VERSION 5.7 ;
BUSBITCHARS "[]" ;
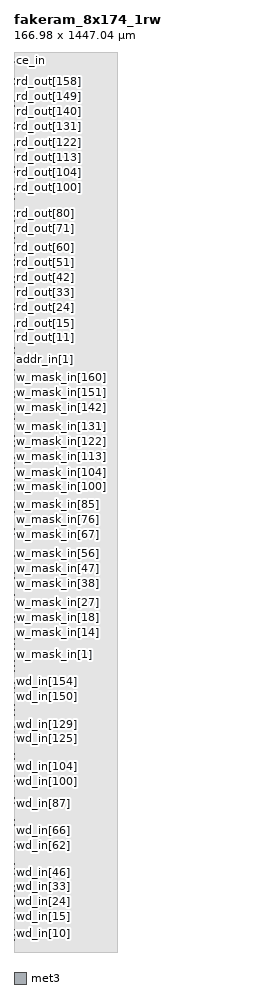
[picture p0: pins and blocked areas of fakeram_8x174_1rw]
MACRO fakeram_8x174_1rw
  FOREIGN fakeram_8x174_1rw 0 0 ;
  SYMMETRY X Y R90 ;
  SIZE 166.980 BY 1447.040 ;
  CLASS BLOCK ;
  PIN wd_in[0]
    DIRECTION INPUT ;
    USE SIGNAL ;
    SHAPE ABUTMENT ;
    PORT
      LAYER met3 ;
      RECT 0.000 2.720 0.300 3.020 ;
    END
  END wd_in[0]
  PIN wd_in[1]
    DIRECTION INPUT ;
    USE SIGNAL ;
    SHAPE ABUTMENT ;
    PORT
      LAYER met3 ;
      RECT 0.000 5.440 0.300 5.740 ;
    END
  END wd_in[1]
  PIN wd_in[2]
    DIRECTION INPUT ;
    USE SIGNAL ;
    SHAPE ABUTMENT ;
    PORT
      LAYER met3 ;
      RECT 0.000 8.160 0.300 8.460 ;
    END
  END wd_in[2]
  PIN wd_in[3]
    DIRECTION INPUT ;
    USE SIGNAL ;
    SHAPE ABUTMENT ;
    PORT
      LAYER met3 ;
      RECT 0.000 10.880 0.300 11.180 ;
    END
  END wd_in[3]
  PIN wd_in[4]
    DIRECTION INPUT ;
    USE SIGNAL ;
    SHAPE ABUTMENT ;
    PORT
      LAYER met3 ;
      RECT 0.000 13.600 0.300 13.900 ;
    END
  END wd_in[4]
  PIN wd_in[5]
    DIRECTION INPUT ;
    USE SIGNAL ;
    SHAPE ABUTMENT ;
    PORT
      LAYER met3 ;
      RECT 0.000 16.320 0.300 16.620 ;
    END
  END wd_in[5]
  PIN wd_in[6]
    DIRECTION INPUT ;
    USE SIGNAL ;
    SHAPE ABUTMENT ;
    PORT
      LAYER met3 ;
      RECT 0.000 19.040 0.300 19.340 ;
    END
  END wd_in[6]
  PIN wd_in[7]
    DIRECTION INPUT ;
    USE SIGNAL ;
    SHAPE ABUTMENT ;
    PORT
      LAYER met3 ;
      RECT 0.000 21.760 0.300 22.060 ;
    END
  END wd_in[7]
  PIN wd_in[8]
    DIRECTION INPUT ;
    USE SIGNAL ;
    SHAPE ABUTMENT ;
    PORT
      LAYER met3 ;
      RECT 0.000 24.480 0.300 24.780 ;
    END
  END wd_in[8]
  PIN wd_in[9]
    DIRECTION INPUT ;
    USE SIGNAL ;
    SHAPE ABUTMENT ;
    PORT
      LAYER met3 ;
      RECT 0.000 27.200 0.300 27.500 ;
    END
  END wd_in[9]
  PIN wd_in[10]
    DIRECTION INPUT ;
    USE SIGNAL ;
    SHAPE ABUTMENT ;
    PORT
      LAYER met3 ;
      RECT 0.000 29.920 0.300 30.220 ;
    END
  END wd_in[10]
  PIN wd_in[11]
    DIRECTION INPUT ;
    USE SIGNAL ;
    SHAPE ABUTMENT ;
    PORT
      LAYER met3 ;
      RECT 0.000 32.640 0.300 32.940 ;
    END
  END wd_in[11]
  PIN wd_in[12]
    DIRECTION INPUT ;
    USE SIGNAL ;
    SHAPE ABUTMENT ;
    PORT
      LAYER met3 ;
      RECT 0.000 35.360 0.300 35.660 ;
    END
  END wd_in[12]
  PIN wd_in[13]
    DIRECTION INPUT ;
    USE SIGNAL ;
    SHAPE ABUTMENT ;
    PORT
      LAYER met3 ;
      RECT 0.000 38.080 0.300 38.380 ;
    END
  END wd_in[13]
  PIN wd_in[14]
    DIRECTION INPUT ;
    USE SIGNAL ;
    SHAPE ABUTMENT ;
    PORT
      LAYER met3 ;
      RECT 0.000 40.800 0.300 41.100 ;
    END
  END wd_in[14]
  PIN wd_in[15]
    DIRECTION INPUT ;
    USE SIGNAL ;
    SHAPE ABUTMENT ;
    PORT
      LAYER met3 ;
      RECT 0.000 43.520 0.300 43.820 ;
    END
  END wd_in[15]
  PIN wd_in[16]
    DIRECTION INPUT ;
    USE SIGNAL ;
    SHAPE ABUTMENT ;
    PORT
      LAYER met3 ;
      RECT 0.000 46.240 0.300 46.540 ;
    END
  END wd_in[16]
  PIN wd_in[17]
    DIRECTION INPUT ;
    USE SIGNAL ;
    SHAPE ABUTMENT ;
    PORT
      LAYER met3 ;
      RECT 0.000 48.960 0.300 49.260 ;
    END
  END wd_in[17]
  PIN wd_in[18]
    DIRECTION INPUT ;
    USE SIGNAL ;
    SHAPE ABUTMENT ;
    PORT
      LAYER met3 ;
      RECT 0.000 51.680 0.300 51.980 ;
    END
  END wd_in[18]
  PIN wd_in[19]
    DIRECTION INPUT ;
    USE SIGNAL ;
    SHAPE ABUTMENT ;
    PORT
      LAYER met3 ;
      RECT 0.000 54.400 0.300 54.700 ;
    END
  END wd_in[19]
  PIN wd_in[20]
    DIRECTION INPUT ;
    USE SIGNAL ;
    SHAPE ABUTMENT ;
    PORT
      LAYER met3 ;
      RECT 0.000 57.120 0.300 57.420 ;
    END
  END wd_in[20]
  PIN wd_in[21]
    DIRECTION INPUT ;
    USE SIGNAL ;
    SHAPE ABUTMENT ;
    PORT
      LAYER met3 ;
      RECT 0.000 59.840 0.300 60.140 ;
    END
  END wd_in[21]
  PIN wd_in[22]
    DIRECTION INPUT ;
    USE SIGNAL ;
    SHAPE ABUTMENT ;
    PORT
      LAYER met3 ;
      RECT 0.000 62.560 0.300 62.860 ;
    END
  END wd_in[22]
  PIN wd_in[23]
    DIRECTION INPUT ;
    USE SIGNAL ;
    SHAPE ABUTMENT ;
    PORT
      LAYER met3 ;
      RECT 0.000 65.280 0.300 65.580 ;
    END
  END wd_in[23]
  PIN wd_in[24]
    DIRECTION INPUT ;
    USE SIGNAL ;
    SHAPE ABUTMENT ;
    PORT
      LAYER met3 ;
      RECT 0.000 68.000 0.300 68.300 ;
    END
  END wd_in[24]
  PIN wd_in[25]
    DIRECTION INPUT ;
    USE SIGNAL ;
    SHAPE ABUTMENT ;
    PORT
      LAYER met3 ;
      RECT 0.000 70.720 0.300 71.020 ;
    END
  END wd_in[25]
  PIN wd_in[26]
    DIRECTION INPUT ;
    USE SIGNAL ;
    SHAPE ABUTMENT ;
    PORT
      LAYER met3 ;
      RECT 0.000 73.440 0.300 73.740 ;
    END
  END wd_in[26]
  PIN wd_in[27]
    DIRECTION INPUT ;
    USE SIGNAL ;
    SHAPE ABUTMENT ;
    PORT
      LAYER met3 ;
      RECT 0.000 76.160 0.300 76.460 ;
    END
  END wd_in[27]
  PIN wd_in[28]
    DIRECTION INPUT ;
    USE SIGNAL ;
    SHAPE ABUTMENT ;
    PORT
      LAYER met3 ;
      RECT 0.000 78.880 0.300 79.180 ;
    END
  END wd_in[28]
  PIN wd_in[29]
    DIRECTION INPUT ;
    USE SIGNAL ;
    SHAPE ABUTMENT ;
    PORT
      LAYER met3 ;
      RECT 0.000 81.600 0.300 81.900 ;
    END
  END wd_in[29]
  PIN wd_in[30]
    DIRECTION INPUT ;
    USE SIGNAL ;
    SHAPE ABUTMENT ;
    PORT
      LAYER met3 ;
      RECT 0.000 84.320 0.300 84.620 ;
    END
  END wd_in[30]
  PIN wd_in[31]
    DIRECTION INPUT ;
    USE SIGNAL ;
    SHAPE ABUTMENT ;
    PORT
      LAYER met3 ;
      RECT 0.000 87.040 0.300 87.340 ;
    END
  END wd_in[31]
  PIN wd_in[32]
    DIRECTION INPUT ;
    USE SIGNAL ;
    SHAPE ABUTMENT ;
    PORT
      LAYER met3 ;
      RECT 0.000 89.760 0.300 90.060 ;
    END
  END wd_in[32]
  PIN wd_in[33]
    DIRECTION INPUT ;
    USE SIGNAL ;
    SHAPE ABUTMENT ;
    PORT
      LAYER met3 ;
      RECT 0.000 92.480 0.300 92.780 ;
    END
  END wd_in[33]
  PIN wd_in[34]
    DIRECTION INPUT ;
    USE SIGNAL ;
    SHAPE ABUTMENT ;
    PORT
      LAYER met3 ;
      RECT 0.000 95.200 0.300 95.500 ;
    END
  END wd_in[34]
  PIN wd_in[35]
    DIRECTION INPUT ;
    USE SIGNAL ;
    SHAPE ABUTMENT ;
    PORT
      LAYER met3 ;
      RECT 0.000 97.920 0.300 98.220 ;
    END
  END wd_in[35]
  PIN wd_in[36]
    DIRECTION INPUT ;
    USE SIGNAL ;
    SHAPE ABUTMENT ;
    PORT
      LAYER met3 ;
      RECT 0.000 100.640 0.300 100.940 ;
    END
  END wd_in[36]
  PIN wd_in[37]
    DIRECTION INPUT ;
    USE SIGNAL ;
    SHAPE ABUTMENT ;
    PORT
      LAYER met3 ;
      RECT 0.000 103.360 0.300 103.660 ;
    END
  END wd_in[37]
  PIN wd_in[38]
    DIRECTION INPUT ;
    USE SIGNAL ;
    SHAPE ABUTMENT ;
    PORT
      LAYER met3 ;
      RECT 0.000 106.080 0.300 106.380 ;
    END
  END wd_in[38]
  PIN wd_in[39]
    DIRECTION INPUT ;
    USE SIGNAL ;
    SHAPE ABUTMENT ;
    PORT
      LAYER met3 ;
      RECT 0.000 108.800 0.300 109.100 ;
    END
  END wd_in[39]
  PIN wd_in[40]
    DIRECTION INPUT ;
    USE SIGNAL ;
    SHAPE ABUTMENT ;
    PORT
      LAYER met3 ;
      RECT 0.000 111.520 0.300 111.820 ;
    END
  END wd_in[40]
  PIN wd_in[41]
    DIRECTION INPUT ;
    USE SIGNAL ;
    SHAPE ABUTMENT ;
    PORT
      LAYER met3 ;
      RECT 0.000 114.240 0.300 114.540 ;
    END
  END wd_in[41]
  PIN wd_in[42]
    DIRECTION INPUT ;
    USE SIGNAL ;
    SHAPE ABUTMENT ;
    PORT
      LAYER met3 ;
      RECT 0.000 116.960 0.300 117.260 ;
    END
  END wd_in[42]
  PIN wd_in[43]
    DIRECTION INPUT ;
    USE SIGNAL ;
    SHAPE ABUTMENT ;
    PORT
      LAYER met3 ;
      RECT 0.000 119.680 0.300 119.980 ;
    END
  END wd_in[43]
  PIN wd_in[44]
    DIRECTION INPUT ;
    USE SIGNAL ;
    SHAPE ABUTMENT ;
    PORT
      LAYER met3 ;
      RECT 0.000 122.400 0.300 122.700 ;
    END
  END wd_in[44]
  PIN wd_in[45]
    DIRECTION INPUT ;
    USE SIGNAL ;
    SHAPE ABUTMENT ;
    PORT
      LAYER met3 ;
      RECT 0.000 125.120 0.300 125.420 ;
    END
  END wd_in[45]
  PIN wd_in[46]
    DIRECTION INPUT ;
    USE SIGNAL ;
    SHAPE ABUTMENT ;
    PORT
      LAYER met3 ;
      RECT 0.000 127.840 0.300 128.140 ;
    END
  END wd_in[46]
  PIN wd_in[47]
    DIRECTION INPUT ;
    USE SIGNAL ;
    SHAPE ABUTMENT ;
    PORT
      LAYER met3 ;
      RECT 0.000 130.560 0.300 130.860 ;
    END
  END wd_in[47]
  PIN wd_in[48]
    DIRECTION INPUT ;
    USE SIGNAL ;
    SHAPE ABUTMENT ;
    PORT
      LAYER met3 ;
      RECT 0.000 133.280 0.300 133.580 ;
    END
  END wd_in[48]
  PIN wd_in[49]
    DIRECTION INPUT ;
    USE SIGNAL ;
    SHAPE ABUTMENT ;
    PORT
      LAYER met3 ;
      RECT 0.000 136.000 0.300 136.300 ;
    END
  END wd_in[49]
  PIN wd_in[50]
    DIRECTION INPUT ;
    USE SIGNAL ;
    SHAPE ABUTMENT ;
    PORT
      LAYER met3 ;
      RECT 0.000 138.720 0.300 139.020 ;
    END
  END wd_in[50]
  PIN wd_in[51]
    DIRECTION INPUT ;
    USE SIGNAL ;
    SHAPE ABUTMENT ;
    PORT
      LAYER met3 ;
      RECT 0.000 141.440 0.300 141.740 ;
    END
  END wd_in[51]
  PIN wd_in[52]
    DIRECTION INPUT ;
    USE SIGNAL ;
    SHAPE ABUTMENT ;
    PORT
      LAYER met3 ;
      RECT 0.000 144.160 0.300 144.460 ;
    END
  END wd_in[52]
  PIN wd_in[53]
    DIRECTION INPUT ;
    USE SIGNAL ;
    SHAPE ABUTMENT ;
    PORT
      LAYER met3 ;
      RECT 0.000 146.880 0.300 147.180 ;
    END
  END wd_in[53]
  PIN wd_in[54]
    DIRECTION INPUT ;
    USE SIGNAL ;
    SHAPE ABUTMENT ;
    PORT
      LAYER met3 ;
      RECT 0.000 149.600 0.300 149.900 ;
    END
  END wd_in[54]
  PIN wd_in[55]
    DIRECTION INPUT ;
    USE SIGNAL ;
    SHAPE ABUTMENT ;
    PORT
      LAYER met3 ;
      RECT 0.000 152.320 0.300 152.620 ;
    END
  END wd_in[55]
  PIN wd_in[56]
    DIRECTION INPUT ;
    USE SIGNAL ;
    SHAPE ABUTMENT ;
    PORT
      LAYER met3 ;
      RECT 0.000 155.040 0.300 155.340 ;
    END
  END wd_in[56]
  PIN wd_in[57]
    DIRECTION INPUT ;
    USE SIGNAL ;
    SHAPE ABUTMENT ;
    PORT
      LAYER met3 ;
      RECT 0.000 157.760 0.300 158.060 ;
    END
  END wd_in[57]
  PIN wd_in[58]
    DIRECTION INPUT ;
    USE SIGNAL ;
    SHAPE ABUTMENT ;
    PORT
      LAYER met3 ;
      RECT 0.000 160.480 0.300 160.780 ;
    END
  END wd_in[58]
  PIN wd_in[59]
    DIRECTION INPUT ;
    USE SIGNAL ;
    SHAPE ABUTMENT ;
    PORT
      LAYER met3 ;
      RECT 0.000 163.200 0.300 163.500 ;
    END
  END wd_in[59]
  PIN wd_in[60]
    DIRECTION INPUT ;
    USE SIGNAL ;
    SHAPE ABUTMENT ;
    PORT
      LAYER met3 ;
      RECT 0.000 165.920 0.300 166.220 ;
    END
  END wd_in[60]
  PIN wd_in[61]
    DIRECTION INPUT ;
    USE SIGNAL ;
    SHAPE ABUTMENT ;
    PORT
      LAYER met3 ;
      RECT 0.000 168.640 0.300 168.940 ;
    END
  END wd_in[61]
  PIN wd_in[62]
    DIRECTION INPUT ;
    USE SIGNAL ;
    SHAPE ABUTMENT ;
    PORT
      LAYER met3 ;
      RECT 0.000 171.360 0.300 171.660 ;
    END
  END wd_in[62]
  PIN wd_in[63]
    DIRECTION INPUT ;
    USE SIGNAL ;
    SHAPE ABUTMENT ;
    PORT
      LAYER met3 ;
      RECT 0.000 174.080 0.300 174.380 ;
    END
  END wd_in[63]
  PIN wd_in[64]
    DIRECTION INPUT ;
    USE SIGNAL ;
    SHAPE ABUTMENT ;
    PORT
      LAYER met3 ;
      RECT 0.000 176.800 0.300 177.100 ;
    END
  END wd_in[64]
  PIN wd_in[65]
    DIRECTION INPUT ;
    USE SIGNAL ;
    SHAPE ABUTMENT ;
    PORT
      LAYER met3 ;
      RECT 0.000 179.520 0.300 179.820 ;
    END
  END wd_in[65]
  PIN wd_in[66]
    DIRECTION INPUT ;
    USE SIGNAL ;
    SHAPE ABUTMENT ;
    PORT
      LAYER met3 ;
      RECT 0.000 182.240 0.300 182.540 ;
    END
  END wd_in[66]
  PIN wd_in[67]
    DIRECTION INPUT ;
    USE SIGNAL ;
    SHAPE ABUTMENT ;
    PORT
      LAYER met3 ;
      RECT 0.000 184.960 0.300 185.260 ;
    END
  END wd_in[67]
  PIN wd_in[68]
    DIRECTION INPUT ;
    USE SIGNAL ;
    SHAPE ABUTMENT ;
    PORT
      LAYER met3 ;
      RECT 0.000 187.680 0.300 187.980 ;
    END
  END wd_in[68]
  PIN wd_in[69]
    DIRECTION INPUT ;
    USE SIGNAL ;
    SHAPE ABUTMENT ;
    PORT
      LAYER met3 ;
      RECT 0.000 190.400 0.300 190.700 ;
    END
  END wd_in[69]
  PIN wd_in[70]
    DIRECTION INPUT ;
    USE SIGNAL ;
    SHAPE ABUTMENT ;
    PORT
      LAYER met3 ;
      RECT 0.000 193.120 0.300 193.420 ;
    END
  END wd_in[70]
  PIN wd_in[71]
    DIRECTION INPUT ;
    USE SIGNAL ;
    SHAPE ABUTMENT ;
    PORT
      LAYER met3 ;
      RECT 0.000 195.840 0.300 196.140 ;
    END
  END wd_in[71]
  PIN wd_in[72]
    DIRECTION INPUT ;
    USE SIGNAL ;
    SHAPE ABUTMENT ;
    PORT
      LAYER met3 ;
      RECT 0.000 198.560 0.300 198.860 ;
    END
  END wd_in[72]
  PIN wd_in[73]
    DIRECTION INPUT ;
    USE SIGNAL ;
    SHAPE ABUTMENT ;
    PORT
      LAYER met3 ;
      RECT 0.000 201.280 0.300 201.580 ;
    END
  END wd_in[73]
  PIN wd_in[74]
    DIRECTION INPUT ;
    USE SIGNAL ;
    SHAPE ABUTMENT ;
    PORT
      LAYER met3 ;
      RECT 0.000 204.000 0.300 204.300 ;
    END
  END wd_in[74]
  PIN wd_in[75]
    DIRECTION INPUT ;
    USE SIGNAL ;
    SHAPE ABUTMENT ;
    PORT
      LAYER met3 ;
      RECT 0.000 206.720 0.300 207.020 ;
    END
  END wd_in[75]
  PIN wd_in[76]
    DIRECTION INPUT ;
    USE SIGNAL ;
    SHAPE ABUTMENT ;
    PORT
      LAYER met3 ;
      RECT 0.000 209.440 0.300 209.740 ;
    END
  END wd_in[76]
  PIN wd_in[77]
    DIRECTION INPUT ;
    USE SIGNAL ;
    SHAPE ABUTMENT ;
    PORT
      LAYER met3 ;
      RECT 0.000 212.160 0.300 212.460 ;
    END
  END wd_in[77]
  PIN wd_in[78]
    DIRECTION INPUT ;
    USE SIGNAL ;
    SHAPE ABUTMENT ;
    PORT
      LAYER met3 ;
      RECT 0.000 214.880 0.300 215.180 ;
    END
  END wd_in[78]
  PIN wd_in[79]
    DIRECTION INPUT ;
    USE SIGNAL ;
    SHAPE ABUTMENT ;
    PORT
      LAYER met3 ;
      RECT 0.000 217.600 0.300 217.900 ;
    END
  END wd_in[79]
  PIN wd_in[80]
    DIRECTION INPUT ;
    USE SIGNAL ;
    SHAPE ABUTMENT ;
    PORT
      LAYER met3 ;
      RECT 0.000 220.320 0.300 220.620 ;
    END
  END wd_in[80]
  PIN wd_in[81]
    DIRECTION INPUT ;
    USE SIGNAL ;
    SHAPE ABUTMENT ;
    PORT
      LAYER met3 ;
      RECT 0.000 223.040 0.300 223.340 ;
    END
  END wd_in[81]
  PIN wd_in[82]
    DIRECTION INPUT ;
    USE SIGNAL ;
    SHAPE ABUTMENT ;
    PORT
      LAYER met3 ;
      RECT 0.000 225.760 0.300 226.060 ;
    END
  END wd_in[82]
  PIN wd_in[83]
    DIRECTION INPUT ;
    USE SIGNAL ;
    SHAPE ABUTMENT ;
    PORT
      LAYER met3 ;
      RECT 0.000 228.480 0.300 228.780 ;
    END
  END wd_in[83]
  PIN wd_in[84]
    DIRECTION INPUT ;
    USE SIGNAL ;
    SHAPE ABUTMENT ;
    PORT
      LAYER met3 ;
      RECT 0.000 231.200 0.300 231.500 ;
    END
  END wd_in[84]
  PIN wd_in[85]
    DIRECTION INPUT ;
    USE SIGNAL ;
    SHAPE ABUTMENT ;
    PORT
      LAYER met3 ;
      RECT 0.000 233.920 0.300 234.220 ;
    END
  END wd_in[85]
  PIN wd_in[86]
    DIRECTION INPUT ;
    USE SIGNAL ;
    SHAPE ABUTMENT ;
    PORT
      LAYER met3 ;
      RECT 0.000 236.640 0.300 236.940 ;
    END
  END wd_in[86]
  PIN wd_in[87]
    DIRECTION INPUT ;
    USE SIGNAL ;
    SHAPE ABUTMENT ;
    PORT
      LAYER met3 ;
      RECT 0.000 239.360 0.300 239.660 ;
    END
  END wd_in[87]
  PIN wd_in[88]
    DIRECTION INPUT ;
    USE SIGNAL ;
    SHAPE ABUTMENT ;
    PORT
      LAYER met3 ;
      RECT 0.000 242.080 0.300 242.380 ;
    END
  END wd_in[88]
  PIN wd_in[89]
    DIRECTION INPUT ;
    USE SIGNAL ;
    SHAPE ABUTMENT ;
    PORT
      LAYER met3 ;
      RECT 0.000 244.800 0.300 245.100 ;
    END
  END wd_in[89]
  PIN wd_in[90]
    DIRECTION INPUT ;
    USE SIGNAL ;
    SHAPE ABUTMENT ;
    PORT
      LAYER met3 ;
      RECT 0.000 247.520 0.300 247.820 ;
    END
  END wd_in[90]
  PIN wd_in[91]
    DIRECTION INPUT ;
    USE SIGNAL ;
    SHAPE ABUTMENT ;
    PORT
      LAYER met3 ;
      RECT 0.000 250.240 0.300 250.540 ;
    END
  END wd_in[91]
  PIN wd_in[92]
    DIRECTION INPUT ;
    USE SIGNAL ;
    SHAPE ABUTMENT ;
    PORT
      LAYER met3 ;
      RECT 0.000 252.960 0.300 253.260 ;
    END
  END wd_in[92]
  PIN wd_in[93]
    DIRECTION INPUT ;
    USE SIGNAL ;
    SHAPE ABUTMENT ;
    PORT
      LAYER met3 ;
      RECT 0.000 255.680 0.300 255.980 ;
    END
  END wd_in[93]
  PIN wd_in[94]
    DIRECTION INPUT ;
    USE SIGNAL ;
    SHAPE ABUTMENT ;
    PORT
      LAYER met3 ;
      RECT 0.000 258.400 0.300 258.700 ;
    END
  END wd_in[94]
  PIN wd_in[95]
    DIRECTION INPUT ;
    USE SIGNAL ;
    SHAPE ABUTMENT ;
    PORT
      LAYER met3 ;
      RECT 0.000 261.120 0.300 261.420 ;
    END
  END wd_in[95]
  PIN wd_in[96]
    DIRECTION INPUT ;
    USE SIGNAL ;
    SHAPE ABUTMENT ;
    PORT
      LAYER met3 ;
      RECT 0.000 263.840 0.300 264.140 ;
    END
  END wd_in[96]
  PIN wd_in[97]
    DIRECTION INPUT ;
    USE SIGNAL ;
    SHAPE ABUTMENT ;
    PORT
      LAYER met3 ;
      RECT 0.000 266.560 0.300 266.860 ;
    END
  END wd_in[97]
  PIN wd_in[98]
    DIRECTION INPUT ;
    USE SIGNAL ;
    SHAPE ABUTMENT ;
    PORT
      LAYER met3 ;
      RECT 0.000 269.280 0.300 269.580 ;
    END
  END wd_in[98]
  PIN wd_in[99]
    DIRECTION INPUT ;
    USE SIGNAL ;
    SHAPE ABUTMENT ;
    PORT
      LAYER met3 ;
      RECT 0.000 272.000 0.300 272.300 ;
    END
  END wd_in[99]
  PIN wd_in[100]
    DIRECTION INPUT ;
    USE SIGNAL ;
    SHAPE ABUTMENT ;
    PORT
      LAYER met3 ;
      RECT 0.000 274.720 0.300 275.020 ;
    END
  END wd_in[100]
  PIN wd_in[101]
    DIRECTION INPUT ;
    USE SIGNAL ;
    SHAPE ABUTMENT ;
    PORT
      LAYER met3 ;
      RECT 0.000 277.440 0.300 277.740 ;
    END
  END wd_in[101]
  PIN wd_in[102]
    DIRECTION INPUT ;
    USE SIGNAL ;
    SHAPE ABUTMENT ;
    PORT
      LAYER met3 ;
      RECT 0.000 280.160 0.300 280.460 ;
    END
  END wd_in[102]
  PIN wd_in[103]
    DIRECTION INPUT ;
    USE SIGNAL ;
    SHAPE ABUTMENT ;
    PORT
      LAYER met3 ;
      RECT 0.000 282.880 0.300 283.180 ;
    END
  END wd_in[103]
  PIN wd_in[104]
    DIRECTION INPUT ;
    USE SIGNAL ;
    SHAPE ABUTMENT ;
    PORT
      LAYER met3 ;
      RECT 0.000 285.600 0.300 285.900 ;
    END
  END wd_in[104]
  PIN wd_in[105]
    DIRECTION INPUT ;
    USE SIGNAL ;
    SHAPE ABUTMENT ;
    PORT
      LAYER met3 ;
      RECT 0.000 288.320 0.300 288.620 ;
    END
  END wd_in[105]
  PIN wd_in[106]
    DIRECTION INPUT ;
    USE SIGNAL ;
    SHAPE ABUTMENT ;
    PORT
      LAYER met3 ;
      RECT 0.000 291.040 0.300 291.340 ;
    END
  END wd_in[106]
  PIN wd_in[107]
    DIRECTION INPUT ;
    USE SIGNAL ;
    SHAPE ABUTMENT ;
    PORT
      LAYER met3 ;
      RECT 0.000 293.760 0.300 294.060 ;
    END
  END wd_in[107]
  PIN wd_in[108]
    DIRECTION INPUT ;
    USE SIGNAL ;
    SHAPE ABUTMENT ;
    PORT
      LAYER met3 ;
      RECT 0.000 296.480 0.300 296.780 ;
    END
  END wd_in[108]
  PIN wd_in[109]
    DIRECTION INPUT ;
    USE SIGNAL ;
    SHAPE ABUTMENT ;
    PORT
      LAYER met3 ;
      RECT 0.000 299.200 0.300 299.500 ;
    END
  END wd_in[109]
  PIN wd_in[110]
    DIRECTION INPUT ;
    USE SIGNAL ;
    SHAPE ABUTMENT ;
    PORT
      LAYER met3 ;
      RECT 0.000 301.920 0.300 302.220 ;
    END
  END wd_in[110]
  PIN wd_in[111]
    DIRECTION INPUT ;
    USE SIGNAL ;
    SHAPE ABUTMENT ;
    PORT
      LAYER met3 ;
      RECT 0.000 304.640 0.300 304.940 ;
    END
  END wd_in[111]
  PIN wd_in[112]
    DIRECTION INPUT ;
    USE SIGNAL ;
    SHAPE ABUTMENT ;
    PORT
      LAYER met3 ;
      RECT 0.000 307.360 0.300 307.660 ;
    END
  END wd_in[112]
  PIN wd_in[113]
    DIRECTION INPUT ;
    USE SIGNAL ;
    SHAPE ABUTMENT ;
    PORT
      LAYER met3 ;
      RECT 0.000 310.080 0.300 310.380 ;
    END
  END wd_in[113]
  PIN wd_in[114]
    DIRECTION INPUT ;
    USE SIGNAL ;
    SHAPE ABUTMENT ;
    PORT
      LAYER met3 ;
      RECT 0.000 312.800 0.300 313.100 ;
    END
  END wd_in[114]
  PIN wd_in[115]
    DIRECTION INPUT ;
    USE SIGNAL ;
    SHAPE ABUTMENT ;
    PORT
      LAYER met3 ;
      RECT 0.000 315.520 0.300 315.820 ;
    END
  END wd_in[115]
  PIN wd_in[116]
    DIRECTION INPUT ;
    USE SIGNAL ;
    SHAPE ABUTMENT ;
    PORT
      LAYER met3 ;
      RECT 0.000 318.240 0.300 318.540 ;
    END
  END wd_in[116]
  PIN wd_in[117]
    DIRECTION INPUT ;
    USE SIGNAL ;
    SHAPE ABUTMENT ;
    PORT
      LAYER met3 ;
      RECT 0.000 320.960 0.300 321.260 ;
    END
  END wd_in[117]
  PIN wd_in[118]
    DIRECTION INPUT ;
    USE SIGNAL ;
    SHAPE ABUTMENT ;
    PORT
      LAYER met3 ;
      RECT 0.000 323.680 0.300 323.980 ;
    END
  END wd_in[118]
  PIN wd_in[119]
    DIRECTION INPUT ;
    USE SIGNAL ;
    SHAPE ABUTMENT ;
    PORT
      LAYER met3 ;
      RECT 0.000 326.400 0.300 326.700 ;
    END
  END wd_in[119]
  PIN wd_in[120]
    DIRECTION INPUT ;
    USE SIGNAL ;
    SHAPE ABUTMENT ;
    PORT
      LAYER met3 ;
      RECT 0.000 329.120 0.300 329.420 ;
    END
  END wd_in[120]
  PIN wd_in[121]
    DIRECTION INPUT ;
    USE SIGNAL ;
    SHAPE ABUTMENT ;
    PORT
      LAYER met3 ;
      RECT 0.000 331.840 0.300 332.140 ;
    END
  END wd_in[121]
  PIN wd_in[122]
    DIRECTION INPUT ;
    USE SIGNAL ;
    SHAPE ABUTMENT ;
    PORT
      LAYER met3 ;
      RECT 0.000 334.560 0.300 334.860 ;
    END
  END wd_in[122]
  PIN wd_in[123]
    DIRECTION INPUT ;
    USE SIGNAL ;
    SHAPE ABUTMENT ;
    PORT
      LAYER met3 ;
      RECT 0.000 337.280 0.300 337.580 ;
    END
  END wd_in[123]
  PIN wd_in[124]
    DIRECTION INPUT ;
    USE SIGNAL ;
    SHAPE ABUTMENT ;
    PORT
      LAYER met3 ;
      RECT 0.000 340.000 0.300 340.300 ;
    END
  END wd_in[124]
  PIN wd_in[125]
    DIRECTION INPUT ;
    USE SIGNAL ;
    SHAPE ABUTMENT ;
    PORT
      LAYER met3 ;
      RECT 0.000 342.720 0.300 343.020 ;
    END
  END wd_in[125]
  PIN wd_in[126]
    DIRECTION INPUT ;
    USE SIGNAL ;
    SHAPE ABUTMENT ;
    PORT
      LAYER met3 ;
      RECT 0.000 345.440 0.300 345.740 ;
    END
  END wd_in[126]
  PIN wd_in[127]
    DIRECTION INPUT ;
    USE SIGNAL ;
    SHAPE ABUTMENT ;
    PORT
      LAYER met3 ;
      RECT 0.000 348.160 0.300 348.460 ;
    END
  END wd_in[127]
  PIN wd_in[128]
    DIRECTION INPUT ;
    USE SIGNAL ;
    SHAPE ABUTMENT ;
    PORT
      LAYER met3 ;
      RECT 0.000 350.880 0.300 351.180 ;
    END
  END wd_in[128]
  PIN wd_in[129]
    DIRECTION INPUT ;
    USE SIGNAL ;
    SHAPE ABUTMENT ;
    PORT
      LAYER met3 ;
      RECT 0.000 353.600 0.300 353.900 ;
    END
  END wd_in[129]
  PIN wd_in[130]
    DIRECTION INPUT ;
    USE SIGNAL ;
    SHAPE ABUTMENT ;
    PORT
      LAYER met3 ;
      RECT 0.000 356.320 0.300 356.620 ;
    END
  END wd_in[130]
  PIN wd_in[131]
    DIRECTION INPUT ;
    USE SIGNAL ;
    SHAPE ABUTMENT ;
    PORT
      LAYER met3 ;
      RECT 0.000 359.040 0.300 359.340 ;
    END
  END wd_in[131]
  PIN wd_in[132]
    DIRECTION INPUT ;
    USE SIGNAL ;
    SHAPE ABUTMENT ;
    PORT
      LAYER met3 ;
      RECT 0.000 361.760 0.300 362.060 ;
    END
  END wd_in[132]
  PIN wd_in[133]
    DIRECTION INPUT ;
    USE SIGNAL ;
    SHAPE ABUTMENT ;
    PORT
      LAYER met3 ;
      RECT 0.000 364.480 0.300 364.780 ;
    END
  END wd_in[133]
  PIN wd_in[134]
    DIRECTION INPUT ;
    USE SIGNAL ;
    SHAPE ABUTMENT ;
    PORT
      LAYER met3 ;
      RECT 0.000 367.200 0.300 367.500 ;
    END
  END wd_in[134]
  PIN wd_in[135]
    DIRECTION INPUT ;
    USE SIGNAL ;
    SHAPE ABUTMENT ;
    PORT
      LAYER met3 ;
      RECT 0.000 369.920 0.300 370.220 ;
    END
  END wd_in[135]
  PIN wd_in[136]
    DIRECTION INPUT ;
    USE SIGNAL ;
    SHAPE ABUTMENT ;
    PORT
      LAYER met3 ;
      RECT 0.000 372.640 0.300 372.940 ;
    END
  END wd_in[136]
  PIN wd_in[137]
    DIRECTION INPUT ;
    USE SIGNAL ;
    SHAPE ABUTMENT ;
    PORT
      LAYER met3 ;
      RECT 0.000 375.360 0.300 375.660 ;
    END
  END wd_in[137]
  PIN wd_in[138]
    DIRECTION INPUT ;
    USE SIGNAL ;
    SHAPE ABUTMENT ;
    PORT
      LAYER met3 ;
      RECT 0.000 378.080 0.300 378.380 ;
    END
  END wd_in[138]
  PIN wd_in[139]
    DIRECTION INPUT ;
    USE SIGNAL ;
    SHAPE ABUTMENT ;
    PORT
      LAYER met3 ;
      RECT 0.000 380.800 0.300 381.100 ;
    END
  END wd_in[139]
  PIN wd_in[140]
    DIRECTION INPUT ;
    USE SIGNAL ;
    SHAPE ABUTMENT ;
    PORT
      LAYER met3 ;
      RECT 0.000 383.520 0.300 383.820 ;
    END
  END wd_in[140]
  PIN wd_in[141]
    DIRECTION INPUT ;
    USE SIGNAL ;
    SHAPE ABUTMENT ;
    PORT
      LAYER met3 ;
      RECT 0.000 386.240 0.300 386.540 ;
    END
  END wd_in[141]
  PIN wd_in[142]
    DIRECTION INPUT ;
    USE SIGNAL ;
    SHAPE ABUTMENT ;
    PORT
      LAYER met3 ;
      RECT 0.000 388.960 0.300 389.260 ;
    END
  END wd_in[142]
  PIN wd_in[143]
    DIRECTION INPUT ;
    USE SIGNAL ;
    SHAPE ABUTMENT ;
    PORT
      LAYER met3 ;
      RECT 0.000 391.680 0.300 391.980 ;
    END
  END wd_in[143]
  PIN wd_in[144]
    DIRECTION INPUT ;
    USE SIGNAL ;
    SHAPE ABUTMENT ;
    PORT
      LAYER met3 ;
      RECT 0.000 394.400 0.300 394.700 ;
    END
  END wd_in[144]
  PIN wd_in[145]
    DIRECTION INPUT ;
    USE SIGNAL ;
    SHAPE ABUTMENT ;
    PORT
      LAYER met3 ;
      RECT 0.000 397.120 0.300 397.420 ;
    END
  END wd_in[145]
  PIN wd_in[146]
    DIRECTION INPUT ;
    USE SIGNAL ;
    SHAPE ABUTMENT ;
    PORT
      LAYER met3 ;
      RECT 0.000 399.840 0.300 400.140 ;
    END
  END wd_in[146]
  PIN wd_in[147]
    DIRECTION INPUT ;
    USE SIGNAL ;
    SHAPE ABUTMENT ;
    PORT
      LAYER met3 ;
      RECT 0.000 402.560 0.300 402.860 ;
    END
  END wd_in[147]
  PIN wd_in[148]
    DIRECTION INPUT ;
    USE SIGNAL ;
    SHAPE ABUTMENT ;
    PORT
      LAYER met3 ;
      RECT 0.000 405.280 0.300 405.580 ;
    END
  END wd_in[148]
  PIN wd_in[149]
    DIRECTION INPUT ;
    USE SIGNAL ;
    SHAPE ABUTMENT ;
    PORT
      LAYER met3 ;
      RECT 0.000 408.000 0.300 408.300 ;
    END
  END wd_in[149]
  PIN wd_in[150]
    DIRECTION INPUT ;
    USE SIGNAL ;
    SHAPE ABUTMENT ;
    PORT
      LAYER met3 ;
      RECT 0.000 410.720 0.300 411.020 ;
    END
  END wd_in[150]
  PIN wd_in[151]
    DIRECTION INPUT ;
    USE SIGNAL ;
    SHAPE ABUTMENT ;
    PORT
      LAYER met3 ;
      RECT 0.000 413.440 0.300 413.740 ;
    END
  END wd_in[151]
  PIN wd_in[152]
    DIRECTION INPUT ;
    USE SIGNAL ;
    SHAPE ABUTMENT ;
    PORT
      LAYER met3 ;
      RECT 0.000 416.160 0.300 416.460 ;
    END
  END wd_in[152]
  PIN wd_in[153]
    DIRECTION INPUT ;
    USE SIGNAL ;
    SHAPE ABUTMENT ;
    PORT
      LAYER met3 ;
      RECT 0.000 418.880 0.300 419.180 ;
    END
  END wd_in[153]
  PIN wd_in[154]
    DIRECTION INPUT ;
    USE SIGNAL ;
    SHAPE ABUTMENT ;
    PORT
      LAYER met3 ;
      RECT 0.000 421.600 0.300 421.900 ;
    END
  END wd_in[154]
  PIN wd_in[155]
    DIRECTION INPUT ;
    USE SIGNAL ;
    SHAPE ABUTMENT ;
    PORT
      LAYER met3 ;
      RECT 0.000 424.320 0.300 424.620 ;
    END
  END wd_in[155]
  PIN wd_in[156]
    DIRECTION INPUT ;
    USE SIGNAL ;
    SHAPE ABUTMENT ;
    PORT
      LAYER met3 ;
      RECT 0.000 427.040 0.300 427.340 ;
    END
  END wd_in[156]
  PIN wd_in[157]
    DIRECTION INPUT ;
    USE SIGNAL ;
    SHAPE ABUTMENT ;
    PORT
      LAYER met3 ;
      RECT 0.000 429.760 0.300 430.060 ;
    END
  END wd_in[157]
  PIN wd_in[158]
    DIRECTION INPUT ;
    USE SIGNAL ;
    SHAPE ABUTMENT ;
    PORT
      LAYER met3 ;
      RECT 0.000 432.480 0.300 432.780 ;
    END
  END wd_in[158]
  PIN wd_in[159]
    DIRECTION INPUT ;
    USE SIGNAL ;
    SHAPE ABUTMENT ;
    PORT
      LAYER met3 ;
      RECT 0.000 435.200 0.300 435.500 ;
    END
  END wd_in[159]
  PIN wd_in[160]
    DIRECTION INPUT ;
    USE SIGNAL ;
    SHAPE ABUTMENT ;
    PORT
      LAYER met3 ;
      RECT 0.000 437.920 0.300 438.220 ;
    END
  END wd_in[160]
  PIN wd_in[161]
    DIRECTION INPUT ;
    USE SIGNAL ;
    SHAPE ABUTMENT ;
    PORT
      LAYER met3 ;
      RECT 0.000 440.640 0.300 440.940 ;
    END
  END wd_in[161]
  PIN wd_in[162]
    DIRECTION INPUT ;
    USE SIGNAL ;
    SHAPE ABUTMENT ;
    PORT
      LAYER met3 ;
      RECT 0.000 443.360 0.300 443.660 ;
    END
  END wd_in[162]
  PIN wd_in[163]
    DIRECTION INPUT ;
    USE SIGNAL ;
    SHAPE ABUTMENT ;
    PORT
      LAYER met3 ;
      RECT 0.000 446.080 0.300 446.380 ;
    END
  END wd_in[163]
  PIN wd_in[164]
    DIRECTION INPUT ;
    USE SIGNAL ;
    SHAPE ABUTMENT ;
    PORT
      LAYER met3 ;
      RECT 0.000 448.800 0.300 449.100 ;
    END
  END wd_in[164]
  PIN wd_in[165]
    DIRECTION INPUT ;
    USE SIGNAL ;
    SHAPE ABUTMENT ;
    PORT
      LAYER met3 ;
      RECT 0.000 451.520 0.300 451.820 ;
    END
  END wd_in[165]
  PIN wd_in[166]
    DIRECTION INPUT ;
    USE SIGNAL ;
    SHAPE ABUTMENT ;
    PORT
      LAYER met3 ;
      RECT 0.000 454.240 0.300 454.540 ;
    END
  END wd_in[166]
  PIN wd_in[167]
    DIRECTION INPUT ;
    USE SIGNAL ;
    SHAPE ABUTMENT ;
    PORT
      LAYER met3 ;
      RECT 0.000 456.960 0.300 457.260 ;
    END
  END wd_in[167]
  PIN wd_in[168]
    DIRECTION INPUT ;
    USE SIGNAL ;
    SHAPE ABUTMENT ;
    PORT
      LAYER met3 ;
      RECT 0.000 459.680 0.300 459.980 ;
    END
  END wd_in[168]
  PIN wd_in[169]
    DIRECTION INPUT ;
    USE SIGNAL ;
    SHAPE ABUTMENT ;
    PORT
      LAYER met3 ;
      RECT 0.000 462.400 0.300 462.700 ;
    END
  END wd_in[169]
  PIN wd_in[170]
    DIRECTION INPUT ;
    USE SIGNAL ;
    SHAPE ABUTMENT ;
    PORT
      LAYER met3 ;
      RECT 0.000 465.120 0.300 465.420 ;
    END
  END wd_in[170]
  PIN wd_in[171]
    DIRECTION INPUT ;
    USE SIGNAL ;
    SHAPE ABUTMENT ;
    PORT
      LAYER met3 ;
      RECT 0.000 467.840 0.300 468.140 ;
    END
  END wd_in[171]
  PIN wd_in[172]
    DIRECTION INPUT ;
    USE SIGNAL ;
    SHAPE ABUTMENT ;
    PORT
      LAYER met3 ;
      RECT 0.000 470.560 0.300 470.860 ;
    END
  END wd_in[172]
  PIN wd_in[173]
    DIRECTION INPUT ;
    USE SIGNAL ;
    SHAPE ABUTMENT ;
    PORT
      LAYER met3 ;
      RECT 0.000 473.280 0.300 473.580 ;
    END
  END wd_in[173]
  PIN w_mask_in[0]
    DIRECTION INPUT ;
    USE SIGNAL ;
    SHAPE ABUTMENT ;
    PORT
      LAYER met3 ;
      RECT 0.000 476.000 0.300 476.300 ;
    END
  END w_mask_in[0]
  PIN w_mask_in[1]
    DIRECTION INPUT ;
    USE SIGNAL ;
    SHAPE ABUTMENT ;
    PORT
      LAYER met3 ;
      RECT 0.000 478.720 0.300 479.020 ;
    END
  END w_mask_in[1]
  PIN w_mask_in[2]
    DIRECTION INPUT ;
    USE SIGNAL ;
    SHAPE ABUTMENT ;
    PORT
      LAYER met3 ;
      RECT 0.000 481.440 0.300 481.740 ;
    END
  END w_mask_in[2]
  PIN w_mask_in[3]
    DIRECTION INPUT ;
    USE SIGNAL ;
    SHAPE ABUTMENT ;
    PORT
      LAYER met3 ;
      RECT 0.000 484.160 0.300 484.460 ;
    END
  END w_mask_in[3]
  PIN w_mask_in[4]
    DIRECTION INPUT ;
    USE SIGNAL ;
    SHAPE ABUTMENT ;
    PORT
      LAYER met3 ;
      RECT 0.000 486.880 0.300 487.180 ;
    END
  END w_mask_in[4]
  PIN w_mask_in[5]
    DIRECTION INPUT ;
    USE SIGNAL ;
    SHAPE ABUTMENT ;
    PORT
      LAYER met3 ;
      RECT 0.000 489.600 0.300 489.900 ;
    END
  END w_mask_in[5]
  PIN w_mask_in[6]
    DIRECTION INPUT ;
    USE SIGNAL ;
    SHAPE ABUTMENT ;
    PORT
      LAYER met3 ;
      RECT 0.000 492.320 0.300 492.620 ;
    END
  END w_mask_in[6]
  PIN w_mask_in[7]
    DIRECTION INPUT ;
    USE SIGNAL ;
    SHAPE ABUTMENT ;
    PORT
      LAYER met3 ;
      RECT 0.000 495.040 0.300 495.340 ;
    END
  END w_mask_in[7]
  PIN w_mask_in[8]
    DIRECTION INPUT ;
    USE SIGNAL ;
    SHAPE ABUTMENT ;
    PORT
      LAYER met3 ;
      RECT 0.000 497.760 0.300 498.060 ;
    END
  END w_mask_in[8]
  PIN w_mask_in[9]
    DIRECTION INPUT ;
    USE SIGNAL ;
    SHAPE ABUTMENT ;
    PORT
      LAYER met3 ;
      RECT 0.000 500.480 0.300 500.780 ;
    END
  END w_mask_in[9]
  PIN w_mask_in[10]
    DIRECTION INPUT ;
    USE SIGNAL ;
    SHAPE ABUTMENT ;
    PORT
      LAYER met3 ;
      RECT 0.000 503.200 0.300 503.500 ;
    END
  END w_mask_in[10]
  PIN w_mask_in[11]
    DIRECTION INPUT ;
    USE SIGNAL ;
    SHAPE ABUTMENT ;
    PORT
      LAYER met3 ;
      RECT 0.000 505.920 0.300 506.220 ;
    END
  END w_mask_in[11]
  PIN w_mask_in[12]
    DIRECTION INPUT ;
    USE SIGNAL ;
    SHAPE ABUTMENT ;
    PORT
      LAYER met3 ;
      RECT 0.000 508.640 0.300 508.940 ;
    END
  END w_mask_in[12]
  PIN w_mask_in[13]
    DIRECTION INPUT ;
    USE SIGNAL ;
    SHAPE ABUTMENT ;
    PORT
      LAYER met3 ;
      RECT 0.000 511.360 0.300 511.660 ;
    END
  END w_mask_in[13]
  PIN w_mask_in[14]
    DIRECTION INPUT ;
    USE SIGNAL ;
    SHAPE ABUTMENT ;
    PORT
      LAYER met3 ;
      RECT 0.000 514.080 0.300 514.380 ;
    END
  END w_mask_in[14]
  PIN w_mask_in[15]
    DIRECTION INPUT ;
    USE SIGNAL ;
    SHAPE ABUTMENT ;
    PORT
      LAYER met3 ;
      RECT 0.000 516.800 0.300 517.100 ;
    END
  END w_mask_in[15]
  PIN w_mask_in[16]
    DIRECTION INPUT ;
    USE SIGNAL ;
    SHAPE ABUTMENT ;
    PORT
      LAYER met3 ;
      RECT 0.000 519.520 0.300 519.820 ;
    END
  END w_mask_in[16]
  PIN w_mask_in[17]
    DIRECTION INPUT ;
    USE SIGNAL ;
    SHAPE ABUTMENT ;
    PORT
      LAYER met3 ;
      RECT 0.000 522.240 0.300 522.540 ;
    END
  END w_mask_in[17]
  PIN w_mask_in[18]
    DIRECTION INPUT ;
    USE SIGNAL ;
    SHAPE ABUTMENT ;
    PORT
      LAYER met3 ;
      RECT 0.000 524.960 0.300 525.260 ;
    END
  END w_mask_in[18]
  PIN w_mask_in[19]
    DIRECTION INPUT ;
    USE SIGNAL ;
    SHAPE ABUTMENT ;
    PORT
      LAYER met3 ;
      RECT 0.000 527.680 0.300 527.980 ;
    END
  END w_mask_in[19]
  PIN w_mask_in[20]
    DIRECTION INPUT ;
    USE SIGNAL ;
    SHAPE ABUTMENT ;
    PORT
      LAYER met3 ;
      RECT 0.000 530.400 0.300 530.700 ;
    END
  END w_mask_in[20]
  PIN w_mask_in[21]
    DIRECTION INPUT ;
    USE SIGNAL ;
    SHAPE ABUTMENT ;
    PORT
      LAYER met3 ;
      RECT 0.000 533.120 0.300 533.420 ;
    END
  END w_mask_in[21]
  PIN w_mask_in[22]
    DIRECTION INPUT ;
    USE SIGNAL ;
    SHAPE ABUTMENT ;
    PORT
      LAYER met3 ;
      RECT 0.000 535.840 0.300 536.140 ;
    END
  END w_mask_in[22]
  PIN w_mask_in[23]
    DIRECTION INPUT ;
    USE SIGNAL ;
    SHAPE ABUTMENT ;
    PORT
      LAYER met3 ;
      RECT 0.000 538.560 0.300 538.860 ;
    END
  END w_mask_in[23]
  PIN w_mask_in[24]
    DIRECTION INPUT ;
    USE SIGNAL ;
    SHAPE ABUTMENT ;
    PORT
      LAYER met3 ;
      RECT 0.000 541.280 0.300 541.580 ;
    END
  END w_mask_in[24]
  PIN w_mask_in[25]
    DIRECTION INPUT ;
    USE SIGNAL ;
    SHAPE ABUTMENT ;
    PORT
      LAYER met3 ;
      RECT 0.000 544.000 0.300 544.300 ;
    END
  END w_mask_in[25]
  PIN w_mask_in[26]
    DIRECTION INPUT ;
    USE SIGNAL ;
    SHAPE ABUTMENT ;
    PORT
      LAYER met3 ;
      RECT 0.000 546.720 0.300 547.020 ;
    END
  END w_mask_in[26]
  PIN w_mask_in[27]
    DIRECTION INPUT ;
    USE SIGNAL ;
    SHAPE ABUTMENT ;
    PORT
      LAYER met3 ;
      RECT 0.000 549.440 0.300 549.740 ;
    END
  END w_mask_in[27]
  PIN w_mask_in[28]
    DIRECTION INPUT ;
    USE SIGNAL ;
    SHAPE ABUTMENT ;
    PORT
      LAYER met3 ;
      RECT 0.000 552.160 0.300 552.460 ;
    END
  END w_mask_in[28]
  PIN w_mask_in[29]
    DIRECTION INPUT ;
    USE SIGNAL ;
    SHAPE ABUTMENT ;
    PORT
      LAYER met3 ;
      RECT 0.000 554.880 0.300 555.180 ;
    END
  END w_mask_in[29]
  PIN w_mask_in[30]
    DIRECTION INPUT ;
    USE SIGNAL ;
    SHAPE ABUTMENT ;
    PORT
      LAYER met3 ;
      RECT 0.000 557.600 0.300 557.900 ;
    END
  END w_mask_in[30]
  PIN w_mask_in[31]
    DIRECTION INPUT ;
    USE SIGNAL ;
    SHAPE ABUTMENT ;
    PORT
      LAYER met3 ;
      RECT 0.000 560.320 0.300 560.620 ;
    END
  END w_mask_in[31]
  PIN w_mask_in[32]
    DIRECTION INPUT ;
    USE SIGNAL ;
    SHAPE ABUTMENT ;
    PORT
      LAYER met3 ;
      RECT 0.000 563.040 0.300 563.340 ;
    END
  END w_mask_in[32]
  PIN w_mask_in[33]
    DIRECTION INPUT ;
    USE SIGNAL ;
    SHAPE ABUTMENT ;
    PORT
      LAYER met3 ;
      RECT 0.000 565.760 0.300 566.060 ;
    END
  END w_mask_in[33]
  PIN w_mask_in[34]
    DIRECTION INPUT ;
    USE SIGNAL ;
    SHAPE ABUTMENT ;
    PORT
      LAYER met3 ;
      RECT 0.000 568.480 0.300 568.780 ;
    END
  END w_mask_in[34]
  PIN w_mask_in[35]
    DIRECTION INPUT ;
    USE SIGNAL ;
    SHAPE ABUTMENT ;
    PORT
      LAYER met3 ;
      RECT 0.000 571.200 0.300 571.500 ;
    END
  END w_mask_in[35]
  PIN w_mask_in[36]
    DIRECTION INPUT ;
    USE SIGNAL ;
    SHAPE ABUTMENT ;
    PORT
      LAYER met3 ;
      RECT 0.000 573.920 0.300 574.220 ;
    END
  END w_mask_in[36]
  PIN w_mask_in[37]
    DIRECTION INPUT ;
    USE SIGNAL ;
    SHAPE ABUTMENT ;
    PORT
      LAYER met3 ;
      RECT 0.000 576.640 0.300 576.940 ;
    END
  END w_mask_in[37]
  PIN w_mask_in[38]
    DIRECTION INPUT ;
    USE SIGNAL ;
    SHAPE ABUTMENT ;
    PORT
      LAYER met3 ;
      RECT 0.000 579.360 0.300 579.660 ;
    END
  END w_mask_in[38]
  PIN w_mask_in[39]
    DIRECTION INPUT ;
    USE SIGNAL ;
    SHAPE ABUTMENT ;
    PORT
      LAYER met3 ;
      RECT 0.000 582.080 0.300 582.380 ;
    END
  END w_mask_in[39]
  PIN w_mask_in[40]
    DIRECTION INPUT ;
    USE SIGNAL ;
    SHAPE ABUTMENT ;
    PORT
      LAYER met3 ;
      RECT 0.000 584.800 0.300 585.100 ;
    END
  END w_mask_in[40]
  PIN w_mask_in[41]
    DIRECTION INPUT ;
    USE SIGNAL ;
    SHAPE ABUTMENT ;
    PORT
      LAYER met3 ;
      RECT 0.000 587.520 0.300 587.820 ;
    END
  END w_mask_in[41]
  PIN w_mask_in[42]
    DIRECTION INPUT ;
    USE SIGNAL ;
    SHAPE ABUTMENT ;
    PORT
      LAYER met3 ;
      RECT 0.000 590.240 0.300 590.540 ;
    END
  END w_mask_in[42]
  PIN w_mask_in[43]
    DIRECTION INPUT ;
    USE SIGNAL ;
    SHAPE ABUTMENT ;
    PORT
      LAYER met3 ;
      RECT 0.000 592.960 0.300 593.260 ;
    END
  END w_mask_in[43]
  PIN w_mask_in[44]
    DIRECTION INPUT ;
    USE SIGNAL ;
    SHAPE ABUTMENT ;
    PORT
      LAYER met3 ;
      RECT 0.000 595.680 0.300 595.980 ;
    END
  END w_mask_in[44]
  PIN w_mask_in[45]
    DIRECTION INPUT ;
    USE SIGNAL ;
    SHAPE ABUTMENT ;
    PORT
      LAYER met3 ;
      RECT 0.000 598.400 0.300 598.700 ;
    END
  END w_mask_in[45]
  PIN w_mask_in[46]
    DIRECTION INPUT ;
    USE SIGNAL ;
    SHAPE ABUTMENT ;
    PORT
      LAYER met3 ;
      RECT 0.000 601.120 0.300 601.420 ;
    END
  END w_mask_in[46]
  PIN w_mask_in[47]
    DIRECTION INPUT ;
    USE SIGNAL ;
    SHAPE ABUTMENT ;
    PORT
      LAYER met3 ;
      RECT 0.000 603.840 0.300 604.140 ;
    END
  END w_mask_in[47]
  PIN w_mask_in[48]
    DIRECTION INPUT ;
    USE SIGNAL ;
    SHAPE ABUTMENT ;
    PORT
      LAYER met3 ;
      RECT 0.000 606.560 0.300 606.860 ;
    END
  END w_mask_in[48]
  PIN w_mask_in[49]
    DIRECTION INPUT ;
    USE SIGNAL ;
    SHAPE ABUTMENT ;
    PORT
      LAYER met3 ;
      RECT 0.000 609.280 0.300 609.580 ;
    END
  END w_mask_in[49]
  PIN w_mask_in[50]
    DIRECTION INPUT ;
    USE SIGNAL ;
    SHAPE ABUTMENT ;
    PORT
      LAYER met3 ;
      RECT 0.000 612.000 0.300 612.300 ;
    END
  END w_mask_in[50]
  PIN w_mask_in[51]
    DIRECTION INPUT ;
    USE SIGNAL ;
    SHAPE ABUTMENT ;
    PORT
      LAYER met3 ;
      RECT 0.000 614.720 0.300 615.020 ;
    END
  END w_mask_in[51]
  PIN w_mask_in[52]
    DIRECTION INPUT ;
    USE SIGNAL ;
    SHAPE ABUTMENT ;
    PORT
      LAYER met3 ;
      RECT 0.000 617.440 0.300 617.740 ;
    END
  END w_mask_in[52]
  PIN w_mask_in[53]
    DIRECTION INPUT ;
    USE SIGNAL ;
    SHAPE ABUTMENT ;
    PORT
      LAYER met3 ;
      RECT 0.000 620.160 0.300 620.460 ;
    END
  END w_mask_in[53]
  PIN w_mask_in[54]
    DIRECTION INPUT ;
    USE SIGNAL ;
    SHAPE ABUTMENT ;
    PORT
      LAYER met3 ;
      RECT 0.000 622.880 0.300 623.180 ;
    END
  END w_mask_in[54]
  PIN w_mask_in[55]
    DIRECTION INPUT ;
    USE SIGNAL ;
    SHAPE ABUTMENT ;
    PORT
      LAYER met3 ;
      RECT 0.000 625.600 0.300 625.900 ;
    END
  END w_mask_in[55]
  PIN w_mask_in[56]
    DIRECTION INPUT ;
    USE SIGNAL ;
    SHAPE ABUTMENT ;
    PORT
      LAYER met3 ;
      RECT 0.000 628.320 0.300 628.620 ;
    END
  END w_mask_in[56]
  PIN w_mask_in[57]
    DIRECTION INPUT ;
    USE SIGNAL ;
    SHAPE ABUTMENT ;
    PORT
      LAYER met3 ;
      RECT 0.000 631.040 0.300 631.340 ;
    END
  END w_mask_in[57]
  PIN w_mask_in[58]
    DIRECTION INPUT ;
    USE SIGNAL ;
    SHAPE ABUTMENT ;
    PORT
      LAYER met3 ;
      RECT 0.000 633.760 0.300 634.060 ;
    END
  END w_mask_in[58]
  PIN w_mask_in[59]
    DIRECTION INPUT ;
    USE SIGNAL ;
    SHAPE ABUTMENT ;
    PORT
      LAYER met3 ;
      RECT 0.000 636.480 0.300 636.780 ;
    END
  END w_mask_in[59]
  PIN w_mask_in[60]
    DIRECTION INPUT ;
    USE SIGNAL ;
    SHAPE ABUTMENT ;
    PORT
      LAYER met3 ;
      RECT 0.000 639.200 0.300 639.500 ;
    END
  END w_mask_in[60]
  PIN w_mask_in[61]
    DIRECTION INPUT ;
    USE SIGNAL ;
    SHAPE ABUTMENT ;
    PORT
      LAYER met3 ;
      RECT 0.000 641.920 0.300 642.220 ;
    END
  END w_mask_in[61]
  PIN w_mask_in[62]
    DIRECTION INPUT ;
    USE SIGNAL ;
    SHAPE ABUTMENT ;
    PORT
      LAYER met3 ;
      RECT 0.000 644.640 0.300 644.940 ;
    END
  END w_mask_in[62]
  PIN w_mask_in[63]
    DIRECTION INPUT ;
    USE SIGNAL ;
    SHAPE ABUTMENT ;
    PORT
      LAYER met3 ;
      RECT 0.000 647.360 0.300 647.660 ;
    END
  END w_mask_in[63]
  PIN w_mask_in[64]
    DIRECTION INPUT ;
    USE SIGNAL ;
    SHAPE ABUTMENT ;
    PORT
      LAYER met3 ;
      RECT 0.000 650.080 0.300 650.380 ;
    END
  END w_mask_in[64]
  PIN w_mask_in[65]
    DIRECTION INPUT ;
    USE SIGNAL ;
    SHAPE ABUTMENT ;
    PORT
      LAYER met3 ;
      RECT 0.000 652.800 0.300 653.100 ;
    END
  END w_mask_in[65]
  PIN w_mask_in[66]
    DIRECTION INPUT ;
    USE SIGNAL ;
    SHAPE ABUTMENT ;
    PORT
      LAYER met3 ;
      RECT 0.000 655.520 0.300 655.820 ;
    END
  END w_mask_in[66]
  PIN w_mask_in[67]
    DIRECTION INPUT ;
    USE SIGNAL ;
    SHAPE ABUTMENT ;
    PORT
      LAYER met3 ;
      RECT 0.000 658.240 0.300 658.540 ;
    END
  END w_mask_in[67]
  PIN w_mask_in[68]
    DIRECTION INPUT ;
    USE SIGNAL ;
    SHAPE ABUTMENT ;
    PORT
      LAYER met3 ;
      RECT 0.000 660.960 0.300 661.260 ;
    END
  END w_mask_in[68]
  PIN w_mask_in[69]
    DIRECTION INPUT ;
    USE SIGNAL ;
    SHAPE ABUTMENT ;
    PORT
      LAYER met3 ;
      RECT 0.000 663.680 0.300 663.980 ;
    END
  END w_mask_in[69]
  PIN w_mask_in[70]
    DIRECTION INPUT ;
    USE SIGNAL ;
    SHAPE ABUTMENT ;
    PORT
      LAYER met3 ;
      RECT 0.000 666.400 0.300 666.700 ;
    END
  END w_mask_in[70]
  PIN w_mask_in[71]
    DIRECTION INPUT ;
    USE SIGNAL ;
    SHAPE ABUTMENT ;
    PORT
      LAYER met3 ;
      RECT 0.000 669.120 0.300 669.420 ;
    END
  END w_mask_in[71]
  PIN w_mask_in[72]
    DIRECTION INPUT ;
    USE SIGNAL ;
    SHAPE ABUTMENT ;
    PORT
      LAYER met3 ;
      RECT 0.000 671.840 0.300 672.140 ;
    END
  END w_mask_in[72]
  PIN w_mask_in[73]
    DIRECTION INPUT ;
    USE SIGNAL ;
    SHAPE ABUTMENT ;
    PORT
      LAYER met3 ;
      RECT 0.000 674.560 0.300 674.860 ;
    END
  END w_mask_in[73]
  PIN w_mask_in[74]
    DIRECTION INPUT ;
    USE SIGNAL ;
    SHAPE ABUTMENT ;
    PORT
      LAYER met3 ;
      RECT 0.000 677.280 0.300 677.580 ;
    END
  END w_mask_in[74]
  PIN w_mask_in[75]
    DIRECTION INPUT ;
    USE SIGNAL ;
    SHAPE ABUTMENT ;
    PORT
      LAYER met3 ;
      RECT 0.000 680.000 0.300 680.300 ;
    END
  END w_mask_in[75]
  PIN w_mask_in[76]
    DIRECTION INPUT ;
    USE SIGNAL ;
    SHAPE ABUTMENT ;
    PORT
      LAYER met3 ;
      RECT 0.000 682.720 0.300 683.020 ;
    END
  END w_mask_in[76]
  PIN w_mask_in[77]
    DIRECTION INPUT ;
    USE SIGNAL ;
    SHAPE ABUTMENT ;
    PORT
      LAYER met3 ;
      RECT 0.000 685.440 0.300 685.740 ;
    END
  END w_mask_in[77]
  PIN w_mask_in[78]
    DIRECTION INPUT ;
    USE SIGNAL ;
    SHAPE ABUTMENT ;
    PORT
      LAYER met3 ;
      RECT 0.000 688.160 0.300 688.460 ;
    END
  END w_mask_in[78]
  PIN w_mask_in[79]
    DIRECTION INPUT ;
    USE SIGNAL ;
    SHAPE ABUTMENT ;
    PORT
      LAYER met3 ;
      RECT 0.000 690.880 0.300 691.180 ;
    END
  END w_mask_in[79]
  PIN w_mask_in[80]
    DIRECTION INPUT ;
    USE SIGNAL ;
    SHAPE ABUTMENT ;
    PORT
      LAYER met3 ;
      RECT 0.000 693.600 0.300 693.900 ;
    END
  END w_mask_in[80]
  PIN w_mask_in[81]
    DIRECTION INPUT ;
    USE SIGNAL ;
    SHAPE ABUTMENT ;
    PORT
      LAYER met3 ;
      RECT 0.000 696.320 0.300 696.620 ;
    END
  END w_mask_in[81]
  PIN w_mask_in[82]
    DIRECTION INPUT ;
    USE SIGNAL ;
    SHAPE ABUTMENT ;
    PORT
      LAYER met3 ;
      RECT 0.000 699.040 0.300 699.340 ;
    END
  END w_mask_in[82]
  PIN w_mask_in[83]
    DIRECTION INPUT ;
    USE SIGNAL ;
    SHAPE ABUTMENT ;
    PORT
      LAYER met3 ;
      RECT 0.000 701.760 0.300 702.060 ;
    END
  END w_mask_in[83]
  PIN w_mask_in[84]
    DIRECTION INPUT ;
    USE SIGNAL ;
    SHAPE ABUTMENT ;
    PORT
      LAYER met3 ;
      RECT 0.000 704.480 0.300 704.780 ;
    END
  END w_mask_in[84]
  PIN w_mask_in[85]
    DIRECTION INPUT ;
    USE SIGNAL ;
    SHAPE ABUTMENT ;
    PORT
      LAYER met3 ;
      RECT 0.000 707.200 0.300 707.500 ;
    END
  END w_mask_in[85]
  PIN w_mask_in[86]
    DIRECTION INPUT ;
    USE SIGNAL ;
    SHAPE ABUTMENT ;
    PORT
      LAYER met3 ;
      RECT 0.000 709.920 0.300 710.220 ;
    END
  END w_mask_in[86]
  PIN w_mask_in[87]
    DIRECTION INPUT ;
    USE SIGNAL ;
    SHAPE ABUTMENT ;
    PORT
      LAYER met3 ;
      RECT 0.000 712.640 0.300 712.940 ;
    END
  END w_mask_in[87]
  PIN w_mask_in[88]
    DIRECTION INPUT ;
    USE SIGNAL ;
    SHAPE ABUTMENT ;
    PORT
      LAYER met3 ;
      RECT 0.000 715.360 0.300 715.660 ;
    END
  END w_mask_in[88]
  PIN w_mask_in[89]
    DIRECTION INPUT ;
    USE SIGNAL ;
    SHAPE ABUTMENT ;
    PORT
      LAYER met3 ;
      RECT 0.000 718.080 0.300 718.380 ;
    END
  END w_mask_in[89]
  PIN w_mask_in[90]
    DIRECTION INPUT ;
    USE SIGNAL ;
    SHAPE ABUTMENT ;
    PORT
      LAYER met3 ;
      RECT 0.000 720.800 0.300 721.100 ;
    END
  END w_mask_in[90]
  PIN w_mask_in[91]
    DIRECTION INPUT ;
    USE SIGNAL ;
    SHAPE ABUTMENT ;
    PORT
      LAYER met3 ;
      RECT 0.000 723.520 0.300 723.820 ;
    END
  END w_mask_in[91]
  PIN w_mask_in[92]
    DIRECTION INPUT ;
    USE SIGNAL ;
    SHAPE ABUTMENT ;
    PORT
      LAYER met3 ;
      RECT 0.000 726.240 0.300 726.540 ;
    END
  END w_mask_in[92]
  PIN w_mask_in[93]
    DIRECTION INPUT ;
    USE SIGNAL ;
    SHAPE ABUTMENT ;
    PORT
      LAYER met3 ;
      RECT 0.000 728.960 0.300 729.260 ;
    END
  END w_mask_in[93]
  PIN w_mask_in[94]
    DIRECTION INPUT ;
    USE SIGNAL ;
    SHAPE ABUTMENT ;
    PORT
      LAYER met3 ;
      RECT 0.000 731.680 0.300 731.980 ;
    END
  END w_mask_in[94]
  PIN w_mask_in[95]
    DIRECTION INPUT ;
    USE SIGNAL ;
    SHAPE ABUTMENT ;
    PORT
      LAYER met3 ;
      RECT 0.000 734.400 0.300 734.700 ;
    END
  END w_mask_in[95]
  PIN w_mask_in[96]
    DIRECTION INPUT ;
    USE SIGNAL ;
    SHAPE ABUTMENT ;
    PORT
      LAYER met3 ;
      RECT 0.000 737.120 0.300 737.420 ;
    END
  END w_mask_in[96]
  PIN w_mask_in[97]
    DIRECTION INPUT ;
    USE SIGNAL ;
    SHAPE ABUTMENT ;
    PORT
      LAYER met3 ;
      RECT 0.000 739.840 0.300 740.140 ;
    END
  END w_mask_in[97]
  PIN w_mask_in[98]
    DIRECTION INPUT ;
    USE SIGNAL ;
    SHAPE ABUTMENT ;
    PORT
      LAYER met3 ;
      RECT 0.000 742.560 0.300 742.860 ;
    END
  END w_mask_in[98]
  PIN w_mask_in[99]
    DIRECTION INPUT ;
    USE SIGNAL ;
    SHAPE ABUTMENT ;
    PORT
      LAYER met3 ;
      RECT 0.000 745.280 0.300 745.580 ;
    END
  END w_mask_in[99]
  PIN w_mask_in[100]
    DIRECTION INPUT ;
    USE SIGNAL ;
    SHAPE ABUTMENT ;
    PORT
      LAYER met3 ;
      RECT 0.000 748.000 0.300 748.300 ;
    END
  END w_mask_in[100]
  PIN w_mask_in[101]
    DIRECTION INPUT ;
    USE SIGNAL ;
    SHAPE ABUTMENT ;
    PORT
      LAYER met3 ;
      RECT 0.000 750.720 0.300 751.020 ;
    END
  END w_mask_in[101]
  PIN w_mask_in[102]
    DIRECTION INPUT ;
    USE SIGNAL ;
    SHAPE ABUTMENT ;
    PORT
      LAYER met3 ;
      RECT 0.000 753.440 0.300 753.740 ;
    END
  END w_mask_in[102]
  PIN w_mask_in[103]
    DIRECTION INPUT ;
    USE SIGNAL ;
    SHAPE ABUTMENT ;
    PORT
      LAYER met3 ;
      RECT 0.000 756.160 0.300 756.460 ;
    END
  END w_mask_in[103]
  PIN w_mask_in[104]
    DIRECTION INPUT ;
    USE SIGNAL ;
    SHAPE ABUTMENT ;
    PORT
      LAYER met3 ;
      RECT 0.000 758.880 0.300 759.180 ;
    END
  END w_mask_in[104]
  PIN w_mask_in[105]
    DIRECTION INPUT ;
    USE SIGNAL ;
    SHAPE ABUTMENT ;
    PORT
      LAYER met3 ;
      RECT 0.000 761.600 0.300 761.900 ;
    END
  END w_mask_in[105]
  PIN w_mask_in[106]
    DIRECTION INPUT ;
    USE SIGNAL ;
    SHAPE ABUTMENT ;
    PORT
      LAYER met3 ;
      RECT 0.000 764.320 0.300 764.620 ;
    END
  END w_mask_in[106]
  PIN w_mask_in[107]
    DIRECTION INPUT ;
    USE SIGNAL ;
    SHAPE ABUTMENT ;
    PORT
      LAYER met3 ;
      RECT 0.000 767.040 0.300 767.340 ;
    END
  END w_mask_in[107]
  PIN w_mask_in[108]
    DIRECTION INPUT ;
    USE SIGNAL ;
    SHAPE ABUTMENT ;
    PORT
      LAYER met3 ;
      RECT 0.000 769.760 0.300 770.060 ;
    END
  END w_mask_in[108]
  PIN w_mask_in[109]
    DIRECTION INPUT ;
    USE SIGNAL ;
    SHAPE ABUTMENT ;
    PORT
      LAYER met3 ;
      RECT 0.000 772.480 0.300 772.780 ;
    END
  END w_mask_in[109]
  PIN w_mask_in[110]
    DIRECTION INPUT ;
    USE SIGNAL ;
    SHAPE ABUTMENT ;
    PORT
      LAYER met3 ;
      RECT 0.000 775.200 0.300 775.500 ;
    END
  END w_mask_in[110]
  PIN w_mask_in[111]
    DIRECTION INPUT ;
    USE SIGNAL ;
    SHAPE ABUTMENT ;
    PORT
      LAYER met3 ;
      RECT 0.000 777.920 0.300 778.220 ;
    END
  END w_mask_in[111]
  PIN w_mask_in[112]
    DIRECTION INPUT ;
    USE SIGNAL ;
    SHAPE ABUTMENT ;
    PORT
      LAYER met3 ;
      RECT 0.000 780.640 0.300 780.940 ;
    END
  END w_mask_in[112]
  PIN w_mask_in[113]
    DIRECTION INPUT ;
    USE SIGNAL ;
    SHAPE ABUTMENT ;
    PORT
      LAYER met3 ;
      RECT 0.000 783.360 0.300 783.660 ;
    END
  END w_mask_in[113]
  PIN w_mask_in[114]
    DIRECTION INPUT ;
    USE SIGNAL ;
    SHAPE ABUTMENT ;
    PORT
      LAYER met3 ;
      RECT 0.000 786.080 0.300 786.380 ;
    END
  END w_mask_in[114]
  PIN w_mask_in[115]
    DIRECTION INPUT ;
    USE SIGNAL ;
    SHAPE ABUTMENT ;
    PORT
      LAYER met3 ;
      RECT 0.000 788.800 0.300 789.100 ;
    END
  END w_mask_in[115]
  PIN w_mask_in[116]
    DIRECTION INPUT ;
    USE SIGNAL ;
    SHAPE ABUTMENT ;
    PORT
      LAYER met3 ;
      RECT 0.000 791.520 0.300 791.820 ;
    END
  END w_mask_in[116]
  PIN w_mask_in[117]
    DIRECTION INPUT ;
    USE SIGNAL ;
    SHAPE ABUTMENT ;
    PORT
      LAYER met3 ;
      RECT 0.000 794.240 0.300 794.540 ;
    END
  END w_mask_in[117]
  PIN w_mask_in[118]
    DIRECTION INPUT ;
    USE SIGNAL ;
    SHAPE ABUTMENT ;
    PORT
      LAYER met3 ;
      RECT 0.000 796.960 0.300 797.260 ;
    END
  END w_mask_in[118]
  PIN w_mask_in[119]
    DIRECTION INPUT ;
    USE SIGNAL ;
    SHAPE ABUTMENT ;
    PORT
      LAYER met3 ;
      RECT 0.000 799.680 0.300 799.980 ;
    END
  END w_mask_in[119]
  PIN w_mask_in[120]
    DIRECTION INPUT ;
    USE SIGNAL ;
    SHAPE ABUTMENT ;
    PORT
      LAYER met3 ;
      RECT 0.000 802.400 0.300 802.700 ;
    END
  END w_mask_in[120]
  PIN w_mask_in[121]
    DIRECTION INPUT ;
    USE SIGNAL ;
    SHAPE ABUTMENT ;
    PORT
      LAYER met3 ;
      RECT 0.000 805.120 0.300 805.420 ;
    END
  END w_mask_in[121]
  PIN w_mask_in[122]
    DIRECTION INPUT ;
    USE SIGNAL ;
    SHAPE ABUTMENT ;
    PORT
      LAYER met3 ;
      RECT 0.000 807.840 0.300 808.140 ;
    END
  END w_mask_in[122]
  PIN w_mask_in[123]
    DIRECTION INPUT ;
    USE SIGNAL ;
    SHAPE ABUTMENT ;
    PORT
      LAYER met3 ;
      RECT 0.000 810.560 0.300 810.860 ;
    END
  END w_mask_in[123]
  PIN w_mask_in[124]
    DIRECTION INPUT ;
    USE SIGNAL ;
    SHAPE ABUTMENT ;
    PORT
      LAYER met3 ;
      RECT 0.000 813.280 0.300 813.580 ;
    END
  END w_mask_in[124]
  PIN w_mask_in[125]
    DIRECTION INPUT ;
    USE SIGNAL ;
    SHAPE ABUTMENT ;
    PORT
      LAYER met3 ;
      RECT 0.000 816.000 0.300 816.300 ;
    END
  END w_mask_in[125]
  PIN w_mask_in[126]
    DIRECTION INPUT ;
    USE SIGNAL ;
    SHAPE ABUTMENT ;
    PORT
      LAYER met3 ;
      RECT 0.000 818.720 0.300 819.020 ;
    END
  END w_mask_in[126]
  PIN w_mask_in[127]
    DIRECTION INPUT ;
    USE SIGNAL ;
    SHAPE ABUTMENT ;
    PORT
      LAYER met3 ;
      RECT 0.000 821.440 0.300 821.740 ;
    END
  END w_mask_in[127]
  PIN w_mask_in[128]
    DIRECTION INPUT ;
    USE SIGNAL ;
    SHAPE ABUTMENT ;
    PORT
      LAYER met3 ;
      RECT 0.000 824.160 0.300 824.460 ;
    END
  END w_mask_in[128]
  PIN w_mask_in[129]
    DIRECTION INPUT ;
    USE SIGNAL ;
    SHAPE ABUTMENT ;
    PORT
      LAYER met3 ;
      RECT 0.000 826.880 0.300 827.180 ;
    END
  END w_mask_in[129]
  PIN w_mask_in[130]
    DIRECTION INPUT ;
    USE SIGNAL ;
    SHAPE ABUTMENT ;
    PORT
      LAYER met3 ;
      RECT 0.000 829.600 0.300 829.900 ;
    END
  END w_mask_in[130]
  PIN w_mask_in[131]
    DIRECTION INPUT ;
    USE SIGNAL ;
    SHAPE ABUTMENT ;
    PORT
      LAYER met3 ;
      RECT 0.000 832.320 0.300 832.620 ;
    END
  END w_mask_in[131]
  PIN w_mask_in[132]
    DIRECTION INPUT ;
    USE SIGNAL ;
    SHAPE ABUTMENT ;
    PORT
      LAYER met3 ;
      RECT 0.000 835.040 0.300 835.340 ;
    END
  END w_mask_in[132]
  PIN w_mask_in[133]
    DIRECTION INPUT ;
    USE SIGNAL ;
    SHAPE ABUTMENT ;
    PORT
      LAYER met3 ;
      RECT 0.000 837.760 0.300 838.060 ;
    END
  END w_mask_in[133]
  PIN w_mask_in[134]
    DIRECTION INPUT ;
    USE SIGNAL ;
    SHAPE ABUTMENT ;
    PORT
      LAYER met3 ;
      RECT 0.000 840.480 0.300 840.780 ;
    END
  END w_mask_in[134]
  PIN w_mask_in[135]
    DIRECTION INPUT ;
    USE SIGNAL ;
    SHAPE ABUTMENT ;
    PORT
      LAYER met3 ;
      RECT 0.000 843.200 0.300 843.500 ;
    END
  END w_mask_in[135]
  PIN w_mask_in[136]
    DIRECTION INPUT ;
    USE SIGNAL ;
    SHAPE ABUTMENT ;
    PORT
      LAYER met3 ;
      RECT 0.000 845.920 0.300 846.220 ;
    END
  END w_mask_in[136]
  PIN w_mask_in[137]
    DIRECTION INPUT ;
    USE SIGNAL ;
    SHAPE ABUTMENT ;
    PORT
      LAYER met3 ;
      RECT 0.000 848.640 0.300 848.940 ;
    END
  END w_mask_in[137]
  PIN w_mask_in[138]
    DIRECTION INPUT ;
    USE SIGNAL ;
    SHAPE ABUTMENT ;
    PORT
      LAYER met3 ;
      RECT 0.000 851.360 0.300 851.660 ;
    END
  END w_mask_in[138]
  PIN w_mask_in[139]
    DIRECTION INPUT ;
    USE SIGNAL ;
    SHAPE ABUTMENT ;
    PORT
      LAYER met3 ;
      RECT 0.000 854.080 0.300 854.380 ;
    END
  END w_mask_in[139]
  PIN w_mask_in[140]
    DIRECTION INPUT ;
    USE SIGNAL ;
    SHAPE ABUTMENT ;
    PORT
      LAYER met3 ;
      RECT 0.000 856.800 0.300 857.100 ;
    END
  END w_mask_in[140]
  PIN w_mask_in[141]
    DIRECTION INPUT ;
    USE SIGNAL ;
    SHAPE ABUTMENT ;
    PORT
      LAYER met3 ;
      RECT 0.000 859.520 0.300 859.820 ;
    END
  END w_mask_in[141]
  PIN w_mask_in[142]
    DIRECTION INPUT ;
    USE SIGNAL ;
    SHAPE ABUTMENT ;
    PORT
      LAYER met3 ;
      RECT 0.000 862.240 0.300 862.540 ;
    END
  END w_mask_in[142]
  PIN w_mask_in[143]
    DIRECTION INPUT ;
    USE SIGNAL ;
    SHAPE ABUTMENT ;
    PORT
      LAYER met3 ;
      RECT 0.000 864.960 0.300 865.260 ;
    END
  END w_mask_in[143]
  PIN w_mask_in[144]
    DIRECTION INPUT ;
    USE SIGNAL ;
    SHAPE ABUTMENT ;
    PORT
      LAYER met3 ;
      RECT 0.000 867.680 0.300 867.980 ;
    END
  END w_mask_in[144]
  PIN w_mask_in[145]
    DIRECTION INPUT ;
    USE SIGNAL ;
    SHAPE ABUTMENT ;
    PORT
      LAYER met3 ;
      RECT 0.000 870.400 0.300 870.700 ;
    END
  END w_mask_in[145]
  PIN w_mask_in[146]
    DIRECTION INPUT ;
    USE SIGNAL ;
    SHAPE ABUTMENT ;
    PORT
      LAYER met3 ;
      RECT 0.000 873.120 0.300 873.420 ;
    END
  END w_mask_in[146]
  PIN w_mask_in[147]
    DIRECTION INPUT ;
    USE SIGNAL ;
    SHAPE ABUTMENT ;
    PORT
      LAYER met3 ;
      RECT 0.000 875.840 0.300 876.140 ;
    END
  END w_mask_in[147]
  PIN w_mask_in[148]
    DIRECTION INPUT ;
    USE SIGNAL ;
    SHAPE ABUTMENT ;
    PORT
      LAYER met3 ;
      RECT 0.000 878.560 0.300 878.860 ;
    END
  END w_mask_in[148]
  PIN w_mask_in[149]
    DIRECTION INPUT ;
    USE SIGNAL ;
    SHAPE ABUTMENT ;
    PORT
      LAYER met3 ;
      RECT 0.000 881.280 0.300 881.580 ;
    END
  END w_mask_in[149]
  PIN w_mask_in[150]
    DIRECTION INPUT ;
    USE SIGNAL ;
    SHAPE ABUTMENT ;
    PORT
      LAYER met3 ;
      RECT 0.000 884.000 0.300 884.300 ;
    END
  END w_mask_in[150]
  PIN w_mask_in[151]
    DIRECTION INPUT ;
    USE SIGNAL ;
    SHAPE ABUTMENT ;
    PORT
      LAYER met3 ;
      RECT 0.000 886.720 0.300 887.020 ;
    END
  END w_mask_in[151]
  PIN w_mask_in[152]
    DIRECTION INPUT ;
    USE SIGNAL ;
    SHAPE ABUTMENT ;
    PORT
      LAYER met3 ;
      RECT 0.000 889.440 0.300 889.740 ;
    END
  END w_mask_in[152]
  PIN w_mask_in[153]
    DIRECTION INPUT ;
    USE SIGNAL ;
    SHAPE ABUTMENT ;
    PORT
      LAYER met3 ;
      RECT 0.000 892.160 0.300 892.460 ;
    END
  END w_mask_in[153]
  PIN w_mask_in[154]
    DIRECTION INPUT ;
    USE SIGNAL ;
    SHAPE ABUTMENT ;
    PORT
      LAYER met3 ;
      RECT 0.000 894.880 0.300 895.180 ;
    END
  END w_mask_in[154]
  PIN w_mask_in[155]
    DIRECTION INPUT ;
    USE SIGNAL ;
    SHAPE ABUTMENT ;
    PORT
      LAYER met3 ;
      RECT 0.000 897.600 0.300 897.900 ;
    END
  END w_mask_in[155]
  PIN w_mask_in[156]
    DIRECTION INPUT ;
    USE SIGNAL ;
    SHAPE ABUTMENT ;
    PORT
      LAYER met3 ;
      RECT 0.000 900.320 0.300 900.620 ;
    END
  END w_mask_in[156]
  PIN w_mask_in[157]
    DIRECTION INPUT ;
    USE SIGNAL ;
    SHAPE ABUTMENT ;
    PORT
      LAYER met3 ;
      RECT 0.000 903.040 0.300 903.340 ;
    END
  END w_mask_in[157]
  PIN w_mask_in[158]
    DIRECTION INPUT ;
    USE SIGNAL ;
    SHAPE ABUTMENT ;
    PORT
      LAYER met3 ;
      RECT 0.000 905.760 0.300 906.060 ;
    END
  END w_mask_in[158]
  PIN w_mask_in[159]
    DIRECTION INPUT ;
    USE SIGNAL ;
    SHAPE ABUTMENT ;
    PORT
      LAYER met3 ;
      RECT 0.000 908.480 0.300 908.780 ;
    END
  END w_mask_in[159]
  PIN w_mask_in[160]
    DIRECTION INPUT ;
    USE SIGNAL ;
    SHAPE ABUTMENT ;
    PORT
      LAYER met3 ;
      RECT 0.000 911.200 0.300 911.500 ;
    END
  END w_mask_in[160]
  PIN w_mask_in[161]
    DIRECTION INPUT ;
    USE SIGNAL ;
    SHAPE ABUTMENT ;
    PORT
      LAYER met3 ;
      RECT 0.000 913.920 0.300 914.220 ;
    END
  END w_mask_in[161]
  PIN w_mask_in[162]
    DIRECTION INPUT ;
    USE SIGNAL ;
    SHAPE ABUTMENT ;
    PORT
      LAYER met3 ;
      RECT 0.000 916.640 0.300 916.940 ;
    END
  END w_mask_in[162]
  PIN w_mask_in[163]
    DIRECTION INPUT ;
    USE SIGNAL ;
    SHAPE ABUTMENT ;
    PORT
      LAYER met3 ;
      RECT 0.000 919.360 0.300 919.660 ;
    END
  END w_mask_in[163]
  PIN w_mask_in[164]
    DIRECTION INPUT ;
    USE SIGNAL ;
    SHAPE ABUTMENT ;
    PORT
      LAYER met3 ;
      RECT 0.000 922.080 0.300 922.380 ;
    END
  END w_mask_in[164]
  PIN w_mask_in[165]
    DIRECTION INPUT ;
    USE SIGNAL ;
    SHAPE ABUTMENT ;
    PORT
      LAYER met3 ;
      RECT 0.000 924.800 0.300 925.100 ;
    END
  END w_mask_in[165]
  PIN w_mask_in[166]
    DIRECTION INPUT ;
    USE SIGNAL ;
    SHAPE ABUTMENT ;
    PORT
      LAYER met3 ;
      RECT 0.000 927.520 0.300 927.820 ;
    END
  END w_mask_in[166]
  PIN w_mask_in[167]
    DIRECTION INPUT ;
    USE SIGNAL ;
    SHAPE ABUTMENT ;
    PORT
      LAYER met3 ;
      RECT 0.000 930.240 0.300 930.540 ;
    END
  END w_mask_in[167]
  PIN w_mask_in[168]
    DIRECTION INPUT ;
    USE SIGNAL ;
    SHAPE ABUTMENT ;
    PORT
      LAYER met3 ;
      RECT 0.000 932.960 0.300 933.260 ;
    END
  END w_mask_in[168]
  PIN w_mask_in[169]
    DIRECTION INPUT ;
    USE SIGNAL ;
    SHAPE ABUTMENT ;
    PORT
      LAYER met3 ;
      RECT 0.000 935.680 0.300 935.980 ;
    END
  END w_mask_in[169]
  PIN w_mask_in[170]
    DIRECTION INPUT ;
    USE SIGNAL ;
    SHAPE ABUTMENT ;
    PORT
      LAYER met3 ;
      RECT 0.000 938.400 0.300 938.700 ;
    END
  END w_mask_in[170]
  PIN w_mask_in[171]
    DIRECTION INPUT ;
    USE SIGNAL ;
    SHAPE ABUTMENT ;
    PORT
      LAYER met3 ;
      RECT 0.000 941.120 0.300 941.420 ;
    END
  END w_mask_in[171]
  PIN w_mask_in[172]
    DIRECTION INPUT ;
    USE SIGNAL ;
    SHAPE ABUTMENT ;
    PORT
      LAYER met3 ;
      RECT 0.000 943.840 0.300 944.140 ;
    END
  END w_mask_in[172]
  PIN w_mask_in[173]
    DIRECTION INPUT ;
    USE SIGNAL ;
    SHAPE ABUTMENT ;
    PORT
      LAYER met3 ;
      RECT 0.000 946.560 0.300 946.860 ;
    END
  END w_mask_in[173]
  PIN addr_in[0]
    DIRECTION INPUT ;
    USE SIGNAL ;
    SHAPE ABUTMENT ;
    PORT
      LAYER met3 ;
      RECT 0.000 949.280 0.300 949.580 ;
    END
  END addr_in[0]
  PIN addr_in[1]
    DIRECTION INPUT ;
    USE SIGNAL ;
    SHAPE ABUTMENT ;
    PORT
      LAYER met3 ;
      RECT 0.000 952.000 0.300 952.300 ;
    END
  END addr_in[1]
  PIN addr_in[2]
    DIRECTION INPUT ;
    USE SIGNAL ;
    SHAPE ABUTMENT ;
    PORT
      LAYER met3 ;
      RECT 0.000 954.720 0.300 955.020 ;
    END
  END addr_in[2]
  PIN rd_out[0]
    DIRECTION OUTPUT ;
    USE SIGNAL ;
    SHAPE ABUTMENT ;
    PORT
      LAYER met3 ;
      RECT 0.000 957.440 0.300 957.740 ;
    END
  END rd_out[0]
  PIN rd_out[1]
    DIRECTION OUTPUT ;
    USE SIGNAL ;
    SHAPE ABUTMENT ;
    PORT
      LAYER met3 ;
      RECT 0.000 960.160 0.300 960.460 ;
    END
  END rd_out[1]
  PIN rd_out[2]
    DIRECTION OUTPUT ;
    USE SIGNAL ;
    SHAPE ABUTMENT ;
    PORT
      LAYER met3 ;
      RECT 0.000 962.880 0.300 963.180 ;
    END
  END rd_out[2]
  PIN rd_out[3]
    DIRECTION OUTPUT ;
    USE SIGNAL ;
    SHAPE ABUTMENT ;
    PORT
      LAYER met3 ;
      RECT 0.000 965.600 0.300 965.900 ;
    END
  END rd_out[3]
  PIN rd_out[4]
    DIRECTION OUTPUT ;
    USE SIGNAL ;
    SHAPE ABUTMENT ;
    PORT
      LAYER met3 ;
      RECT 0.000 968.320 0.300 968.620 ;
    END
  END rd_out[4]
  PIN rd_out[5]
    DIRECTION OUTPUT ;
    USE SIGNAL ;
    SHAPE ABUTMENT ;
    PORT
      LAYER met3 ;
      RECT 0.000 971.040 0.300 971.340 ;
    END
  END rd_out[5]
  PIN rd_out[6]
    DIRECTION OUTPUT ;
    USE SIGNAL ;
    SHAPE ABUTMENT ;
    PORT
      LAYER met3 ;
      RECT 0.000 973.760 0.300 974.060 ;
    END
  END rd_out[6]
  PIN rd_out[7]
    DIRECTION OUTPUT ;
    USE SIGNAL ;
    SHAPE ABUTMENT ;
    PORT
      LAYER met3 ;
      RECT 0.000 976.480 0.300 976.780 ;
    END
  END rd_out[7]
  PIN rd_out[8]
    DIRECTION OUTPUT ;
    USE SIGNAL ;
    SHAPE ABUTMENT ;
    PORT
      LAYER met3 ;
      RECT 0.000 979.200 0.300 979.500 ;
    END
  END rd_out[8]
  PIN rd_out[9]
    DIRECTION OUTPUT ;
    USE SIGNAL ;
    SHAPE ABUTMENT ;
    PORT
      LAYER met3 ;
      RECT 0.000 981.920 0.300 982.220 ;
    END
  END rd_out[9]
  PIN rd_out[10]
    DIRECTION OUTPUT ;
    USE SIGNAL ;
    SHAPE ABUTMENT ;
    PORT
      LAYER met3 ;
      RECT 0.000 984.640 0.300 984.940 ;
    END
  END rd_out[10]
  PIN rd_out[11]
    DIRECTION OUTPUT ;
    USE SIGNAL ;
    SHAPE ABUTMENT ;
    PORT
      LAYER met3 ;
      RECT 0.000 987.360 0.300 987.660 ;
    END
  END rd_out[11]
  PIN rd_out[12]
    DIRECTION OUTPUT ;
    USE SIGNAL ;
    SHAPE ABUTMENT ;
    PORT
      LAYER met3 ;
      RECT 0.000 990.080 0.300 990.380 ;
    END
  END rd_out[12]
  PIN rd_out[13]
    DIRECTION OUTPUT ;
    USE SIGNAL ;
    SHAPE ABUTMENT ;
    PORT
      LAYER met3 ;
      RECT 0.000 992.800 0.300 993.100 ;
    END
  END rd_out[13]
  PIN rd_out[14]
    DIRECTION OUTPUT ;
    USE SIGNAL ;
    SHAPE ABUTMENT ;
    PORT
      LAYER met3 ;
      RECT 0.000 995.520 0.300 995.820 ;
    END
  END rd_out[14]
  PIN rd_out[15]
    DIRECTION OUTPUT ;
    USE SIGNAL ;
    SHAPE ABUTMENT ;
    PORT
      LAYER met3 ;
      RECT 0.000 998.240 0.300 998.540 ;
    END
  END rd_out[15]
  PIN rd_out[16]
    DIRECTION OUTPUT ;
    USE SIGNAL ;
    SHAPE ABUTMENT ;
    PORT
      LAYER met3 ;
      RECT 0.000 1000.960 0.300 1001.260 ;
    END
  END rd_out[16]
  PIN rd_out[17]
    DIRECTION OUTPUT ;
    USE SIGNAL ;
    SHAPE ABUTMENT ;
    PORT
      LAYER met3 ;
      RECT 0.000 1003.680 0.300 1003.980 ;
    END
  END rd_out[17]
  PIN rd_out[18]
    DIRECTION OUTPUT ;
    USE SIGNAL ;
    SHAPE ABUTMENT ;
    PORT
      LAYER met3 ;
      RECT 0.000 1006.400 0.300 1006.700 ;
    END
  END rd_out[18]
  PIN rd_out[19]
    DIRECTION OUTPUT ;
    USE SIGNAL ;
    SHAPE ABUTMENT ;
    PORT
      LAYER met3 ;
      RECT 0.000 1009.120 0.300 1009.420 ;
    END
  END rd_out[19]
  PIN rd_out[20]
    DIRECTION OUTPUT ;
    USE SIGNAL ;
    SHAPE ABUTMENT ;
    PORT
      LAYER met3 ;
      RECT 0.000 1011.840 0.300 1012.140 ;
    END
  END rd_out[20]
  PIN rd_out[21]
    DIRECTION OUTPUT ;
    USE SIGNAL ;
    SHAPE ABUTMENT ;
    PORT
      LAYER met3 ;
      RECT 0.000 1014.560 0.300 1014.860 ;
    END
  END rd_out[21]
  PIN rd_out[22]
    DIRECTION OUTPUT ;
    USE SIGNAL ;
    SHAPE ABUTMENT ;
    PORT
      LAYER met3 ;
      RECT 0.000 1017.280 0.300 1017.580 ;
    END
  END rd_out[22]
  PIN rd_out[23]
    DIRECTION OUTPUT ;
    USE SIGNAL ;
    SHAPE ABUTMENT ;
    PORT
      LAYER met3 ;
      RECT 0.000 1020.000 0.300 1020.300 ;
    END
  END rd_out[23]
  PIN rd_out[24]
    DIRECTION OUTPUT ;
    USE SIGNAL ;
    SHAPE ABUTMENT ;
    PORT
      LAYER met3 ;
      RECT 0.000 1022.720 0.300 1023.020 ;
    END
  END rd_out[24]
  PIN rd_out[25]
    DIRECTION OUTPUT ;
    USE SIGNAL ;
    SHAPE ABUTMENT ;
    PORT
      LAYER met3 ;
      RECT 0.000 1025.440 0.300 1025.740 ;
    END
  END rd_out[25]
  PIN rd_out[26]
    DIRECTION OUTPUT ;
    USE SIGNAL ;
    SHAPE ABUTMENT ;
    PORT
      LAYER met3 ;
      RECT 0.000 1028.160 0.300 1028.460 ;
    END
  END rd_out[26]
  PIN rd_out[27]
    DIRECTION OUTPUT ;
    USE SIGNAL ;
    SHAPE ABUTMENT ;
    PORT
      LAYER met3 ;
      RECT 0.000 1030.880 0.300 1031.180 ;
    END
  END rd_out[27]
  PIN rd_out[28]
    DIRECTION OUTPUT ;
    USE SIGNAL ;
    SHAPE ABUTMENT ;
    PORT
      LAYER met3 ;
      RECT 0.000 1033.600 0.300 1033.900 ;
    END
  END rd_out[28]
  PIN rd_out[29]
    DIRECTION OUTPUT ;
    USE SIGNAL ;
    SHAPE ABUTMENT ;
    PORT
      LAYER met3 ;
      RECT 0.000 1036.320 0.300 1036.620 ;
    END
  END rd_out[29]
  PIN rd_out[30]
    DIRECTION OUTPUT ;
    USE SIGNAL ;
    SHAPE ABUTMENT ;
    PORT
      LAYER met3 ;
      RECT 0.000 1039.040 0.300 1039.340 ;
    END
  END rd_out[30]
  PIN rd_out[31]
    DIRECTION OUTPUT ;
    USE SIGNAL ;
    SHAPE ABUTMENT ;
    PORT
      LAYER met3 ;
      RECT 0.000 1041.760 0.300 1042.060 ;
    END
  END rd_out[31]
  PIN rd_out[32]
    DIRECTION OUTPUT ;
    USE SIGNAL ;
    SHAPE ABUTMENT ;
    PORT
      LAYER met3 ;
      RECT 0.000 1044.480 0.300 1044.780 ;
    END
  END rd_out[32]
  PIN rd_out[33]
    DIRECTION OUTPUT ;
    USE SIGNAL ;
    SHAPE ABUTMENT ;
    PORT
      LAYER met3 ;
      RECT 0.000 1047.200 0.300 1047.500 ;
    END
  END rd_out[33]
  PIN rd_out[34]
    DIRECTION OUTPUT ;
    USE SIGNAL ;
    SHAPE ABUTMENT ;
    PORT
      LAYER met3 ;
      RECT 0.000 1049.920 0.300 1050.220 ;
    END
  END rd_out[34]
  PIN rd_out[35]
    DIRECTION OUTPUT ;
    USE SIGNAL ;
    SHAPE ABUTMENT ;
    PORT
      LAYER met3 ;
      RECT 0.000 1052.640 0.300 1052.940 ;
    END
  END rd_out[35]
  PIN rd_out[36]
    DIRECTION OUTPUT ;
    USE SIGNAL ;
    SHAPE ABUTMENT ;
    PORT
      LAYER met3 ;
      RECT 0.000 1055.360 0.300 1055.660 ;
    END
  END rd_out[36]
  PIN rd_out[37]
    DIRECTION OUTPUT ;
    USE SIGNAL ;
    SHAPE ABUTMENT ;
    PORT
      LAYER met3 ;
      RECT 0.000 1058.080 0.300 1058.380 ;
    END
  END rd_out[37]
  PIN rd_out[38]
    DIRECTION OUTPUT ;
    USE SIGNAL ;
    SHAPE ABUTMENT ;
    PORT
      LAYER met3 ;
      RECT 0.000 1060.800 0.300 1061.100 ;
    END
  END rd_out[38]
  PIN rd_out[39]
    DIRECTION OUTPUT ;
    USE SIGNAL ;
    SHAPE ABUTMENT ;
    PORT
      LAYER met3 ;
      RECT 0.000 1063.520 0.300 1063.820 ;
    END
  END rd_out[39]
  PIN rd_out[40]
    DIRECTION OUTPUT ;
    USE SIGNAL ;
    SHAPE ABUTMENT ;
    PORT
      LAYER met3 ;
      RECT 0.000 1066.240 0.300 1066.540 ;
    END
  END rd_out[40]
  PIN rd_out[41]
    DIRECTION OUTPUT ;
    USE SIGNAL ;
    SHAPE ABUTMENT ;
    PORT
      LAYER met3 ;
      RECT 0.000 1068.960 0.300 1069.260 ;
    END
  END rd_out[41]
  PIN rd_out[42]
    DIRECTION OUTPUT ;
    USE SIGNAL ;
    SHAPE ABUTMENT ;
    PORT
      LAYER met3 ;
      RECT 0.000 1071.680 0.300 1071.980 ;
    END
  END rd_out[42]
  PIN rd_out[43]
    DIRECTION OUTPUT ;
    USE SIGNAL ;
    SHAPE ABUTMENT ;
    PORT
      LAYER met3 ;
      RECT 0.000 1074.400 0.300 1074.700 ;
    END
  END rd_out[43]
  PIN rd_out[44]
    DIRECTION OUTPUT ;
    USE SIGNAL ;
    SHAPE ABUTMENT ;
    PORT
      LAYER met3 ;
      RECT 0.000 1077.120 0.300 1077.420 ;
    END
  END rd_out[44]
  PIN rd_out[45]
    DIRECTION OUTPUT ;
    USE SIGNAL ;
    SHAPE ABUTMENT ;
    PORT
      LAYER met3 ;
      RECT 0.000 1079.840 0.300 1080.140 ;
    END
  END rd_out[45]
  PIN rd_out[46]
    DIRECTION OUTPUT ;
    USE SIGNAL ;
    SHAPE ABUTMENT ;
    PORT
      LAYER met3 ;
      RECT 0.000 1082.560 0.300 1082.860 ;
    END
  END rd_out[46]
  PIN rd_out[47]
    DIRECTION OUTPUT ;
    USE SIGNAL ;
    SHAPE ABUTMENT ;
    PORT
      LAYER met3 ;
      RECT 0.000 1085.280 0.300 1085.580 ;
    END
  END rd_out[47]
  PIN rd_out[48]
    DIRECTION OUTPUT ;
    USE SIGNAL ;
    SHAPE ABUTMENT ;
    PORT
      LAYER met3 ;
      RECT 0.000 1088.000 0.300 1088.300 ;
    END
  END rd_out[48]
  PIN rd_out[49]
    DIRECTION OUTPUT ;
    USE SIGNAL ;
    SHAPE ABUTMENT ;
    PORT
      LAYER met3 ;
      RECT 0.000 1090.720 0.300 1091.020 ;
    END
  END rd_out[49]
  PIN rd_out[50]
    DIRECTION OUTPUT ;
    USE SIGNAL ;
    SHAPE ABUTMENT ;
    PORT
      LAYER met3 ;
      RECT 0.000 1093.440 0.300 1093.740 ;
    END
  END rd_out[50]
  PIN rd_out[51]
    DIRECTION OUTPUT ;
    USE SIGNAL ;
    SHAPE ABUTMENT ;
    PORT
      LAYER met3 ;
      RECT 0.000 1096.160 0.300 1096.460 ;
    END
  END rd_out[51]
  PIN rd_out[52]
    DIRECTION OUTPUT ;
    USE SIGNAL ;
    SHAPE ABUTMENT ;
    PORT
      LAYER met3 ;
      RECT 0.000 1098.880 0.300 1099.180 ;
    END
  END rd_out[52]
  PIN rd_out[53]
    DIRECTION OUTPUT ;
    USE SIGNAL ;
    SHAPE ABUTMENT ;
    PORT
      LAYER met3 ;
      RECT 0.000 1101.600 0.300 1101.900 ;
    END
  END rd_out[53]
  PIN rd_out[54]
    DIRECTION OUTPUT ;
    USE SIGNAL ;
    SHAPE ABUTMENT ;
    PORT
      LAYER met3 ;
      RECT 0.000 1104.320 0.300 1104.620 ;
    END
  END rd_out[54]
  PIN rd_out[55]
    DIRECTION OUTPUT ;
    USE SIGNAL ;
    SHAPE ABUTMENT ;
    PORT
      LAYER met3 ;
      RECT 0.000 1107.040 0.300 1107.340 ;
    END
  END rd_out[55]
  PIN rd_out[56]
    DIRECTION OUTPUT ;
    USE SIGNAL ;
    SHAPE ABUTMENT ;
    PORT
      LAYER met3 ;
      RECT 0.000 1109.760 0.300 1110.060 ;
    END
  END rd_out[56]
  PIN rd_out[57]
    DIRECTION OUTPUT ;
    USE SIGNAL ;
    SHAPE ABUTMENT ;
    PORT
      LAYER met3 ;
      RECT 0.000 1112.480 0.300 1112.780 ;
    END
  END rd_out[57]
  PIN rd_out[58]
    DIRECTION OUTPUT ;
    USE SIGNAL ;
    SHAPE ABUTMENT ;
    PORT
      LAYER met3 ;
      RECT 0.000 1115.200 0.300 1115.500 ;
    END
  END rd_out[58]
  PIN rd_out[59]
    DIRECTION OUTPUT ;
    USE SIGNAL ;
    SHAPE ABUTMENT ;
    PORT
      LAYER met3 ;
      RECT 0.000 1117.920 0.300 1118.220 ;
    END
  END rd_out[59]
  PIN rd_out[60]
    DIRECTION OUTPUT ;
    USE SIGNAL ;
    SHAPE ABUTMENT ;
    PORT
      LAYER met3 ;
      RECT 0.000 1120.640 0.300 1120.940 ;
    END
  END rd_out[60]
  PIN rd_out[61]
    DIRECTION OUTPUT ;
    USE SIGNAL ;
    SHAPE ABUTMENT ;
    PORT
      LAYER met3 ;
      RECT 0.000 1123.360 0.300 1123.660 ;
    END
  END rd_out[61]
  PIN rd_out[62]
    DIRECTION OUTPUT ;
    USE SIGNAL ;
    SHAPE ABUTMENT ;
    PORT
      LAYER met3 ;
      RECT 0.000 1126.080 0.300 1126.380 ;
    END
  END rd_out[62]
  PIN rd_out[63]
    DIRECTION OUTPUT ;
    USE SIGNAL ;
    SHAPE ABUTMENT ;
    PORT
      LAYER met3 ;
      RECT 0.000 1128.800 0.300 1129.100 ;
    END
  END rd_out[63]
  PIN rd_out[64]
    DIRECTION OUTPUT ;
    USE SIGNAL ;
    SHAPE ABUTMENT ;
    PORT
      LAYER met3 ;
      RECT 0.000 1131.520 0.300 1131.820 ;
    END
  END rd_out[64]
  PIN rd_out[65]
    DIRECTION OUTPUT ;
    USE SIGNAL ;
    SHAPE ABUTMENT ;
    PORT
      LAYER met3 ;
      RECT 0.000 1134.240 0.300 1134.540 ;
    END
  END rd_out[65]
  PIN rd_out[66]
    DIRECTION OUTPUT ;
    USE SIGNAL ;
    SHAPE ABUTMENT ;
    PORT
      LAYER met3 ;
      RECT 0.000 1136.960 0.300 1137.260 ;
    END
  END rd_out[66]
  PIN rd_out[67]
    DIRECTION OUTPUT ;
    USE SIGNAL ;
    SHAPE ABUTMENT ;
    PORT
      LAYER met3 ;
      RECT 0.000 1139.680 0.300 1139.980 ;
    END
  END rd_out[67]
  PIN rd_out[68]
    DIRECTION OUTPUT ;
    USE SIGNAL ;
    SHAPE ABUTMENT ;
    PORT
      LAYER met3 ;
      RECT 0.000 1142.400 0.300 1142.700 ;
    END
  END rd_out[68]
  PIN rd_out[69]
    DIRECTION OUTPUT ;
    USE SIGNAL ;
    SHAPE ABUTMENT ;
    PORT
      LAYER met3 ;
      RECT 0.000 1145.120 0.300 1145.420 ;
    END
  END rd_out[69]
  PIN rd_out[70]
    DIRECTION OUTPUT ;
    USE SIGNAL ;
    SHAPE ABUTMENT ;
    PORT
      LAYER met3 ;
      RECT 0.000 1147.840 0.300 1148.140 ;
    END
  END rd_out[70]
  PIN rd_out[71]
    DIRECTION OUTPUT ;
    USE SIGNAL ;
    SHAPE ABUTMENT ;
    PORT
      LAYER met3 ;
      RECT 0.000 1150.560 0.300 1150.860 ;
    END
  END rd_out[71]
  PIN rd_out[72]
    DIRECTION OUTPUT ;
    USE SIGNAL ;
    SHAPE ABUTMENT ;
    PORT
      LAYER met3 ;
      RECT 0.000 1153.280 0.300 1153.580 ;
    END
  END rd_out[72]
  PIN rd_out[73]
    DIRECTION OUTPUT ;
    USE SIGNAL ;
    SHAPE ABUTMENT ;
    PORT
      LAYER met3 ;
      RECT 0.000 1156.000 0.300 1156.300 ;
    END
  END rd_out[73]
  PIN rd_out[74]
    DIRECTION OUTPUT ;
    USE SIGNAL ;
    SHAPE ABUTMENT ;
    PORT
      LAYER met3 ;
      RECT 0.000 1158.720 0.300 1159.020 ;
    END
  END rd_out[74]
  PIN rd_out[75]
    DIRECTION OUTPUT ;
    USE SIGNAL ;
    SHAPE ABUTMENT ;
    PORT
      LAYER met3 ;
      RECT 0.000 1161.440 0.300 1161.740 ;
    END
  END rd_out[75]
  PIN rd_out[76]
    DIRECTION OUTPUT ;
    USE SIGNAL ;
    SHAPE ABUTMENT ;
    PORT
      LAYER met3 ;
      RECT 0.000 1164.160 0.300 1164.460 ;
    END
  END rd_out[76]
  PIN rd_out[77]
    DIRECTION OUTPUT ;
    USE SIGNAL ;
    SHAPE ABUTMENT ;
    PORT
      LAYER met3 ;
      RECT 0.000 1166.880 0.300 1167.180 ;
    END
  END rd_out[77]
  PIN rd_out[78]
    DIRECTION OUTPUT ;
    USE SIGNAL ;
    SHAPE ABUTMENT ;
    PORT
      LAYER met3 ;
      RECT 0.000 1169.600 0.300 1169.900 ;
    END
  END rd_out[78]
  PIN rd_out[79]
    DIRECTION OUTPUT ;
    USE SIGNAL ;
    SHAPE ABUTMENT ;
    PORT
      LAYER met3 ;
      RECT 0.000 1172.320 0.300 1172.620 ;
    END
  END rd_out[79]
  PIN rd_out[80]
    DIRECTION OUTPUT ;
    USE SIGNAL ;
    SHAPE ABUTMENT ;
    PORT
      LAYER met3 ;
      RECT 0.000 1175.040 0.300 1175.340 ;
    END
  END rd_out[80]
  PIN rd_out[81]
    DIRECTION OUTPUT ;
    USE SIGNAL ;
    SHAPE ABUTMENT ;
    PORT
      LAYER met3 ;
      RECT 0.000 1177.760 0.300 1178.060 ;
    END
  END rd_out[81]
  PIN rd_out[82]
    DIRECTION OUTPUT ;
    USE SIGNAL ;
    SHAPE ABUTMENT ;
    PORT
      LAYER met3 ;
      RECT 0.000 1180.480 0.300 1180.780 ;
    END
  END rd_out[82]
  PIN rd_out[83]
    DIRECTION OUTPUT ;
    USE SIGNAL ;
    SHAPE ABUTMENT ;
    PORT
      LAYER met3 ;
      RECT 0.000 1183.200 0.300 1183.500 ;
    END
  END rd_out[83]
  PIN rd_out[84]
    DIRECTION OUTPUT ;
    USE SIGNAL ;
    SHAPE ABUTMENT ;
    PORT
      LAYER met3 ;
      RECT 0.000 1185.920 0.300 1186.220 ;
    END
  END rd_out[84]
  PIN rd_out[85]
    DIRECTION OUTPUT ;
    USE SIGNAL ;
    SHAPE ABUTMENT ;
    PORT
      LAYER met3 ;
      RECT 0.000 1188.640 0.300 1188.940 ;
    END
  END rd_out[85]
  PIN rd_out[86]
    DIRECTION OUTPUT ;
    USE SIGNAL ;
    SHAPE ABUTMENT ;
    PORT
      LAYER met3 ;
      RECT 0.000 1191.360 0.300 1191.660 ;
    END
  END rd_out[86]
  PIN rd_out[87]
    DIRECTION OUTPUT ;
    USE SIGNAL ;
    SHAPE ABUTMENT ;
    PORT
      LAYER met3 ;
      RECT 0.000 1194.080 0.300 1194.380 ;
    END
  END rd_out[87]
  PIN rd_out[88]
    DIRECTION OUTPUT ;
    USE SIGNAL ;
    SHAPE ABUTMENT ;
    PORT
      LAYER met3 ;
      RECT 0.000 1196.800 0.300 1197.100 ;
    END
  END rd_out[88]
  PIN rd_out[89]
    DIRECTION OUTPUT ;
    USE SIGNAL ;
    SHAPE ABUTMENT ;
    PORT
      LAYER met3 ;
      RECT 0.000 1199.520 0.300 1199.820 ;
    END
  END rd_out[89]
  PIN rd_out[90]
    DIRECTION OUTPUT ;
    USE SIGNAL ;
    SHAPE ABUTMENT ;
    PORT
      LAYER met3 ;
      RECT 0.000 1202.240 0.300 1202.540 ;
    END
  END rd_out[90]
  PIN rd_out[91]
    DIRECTION OUTPUT ;
    USE SIGNAL ;
    SHAPE ABUTMENT ;
    PORT
      LAYER met3 ;
      RECT 0.000 1204.960 0.300 1205.260 ;
    END
  END rd_out[91]
  PIN rd_out[92]
    DIRECTION OUTPUT ;
    USE SIGNAL ;
    SHAPE ABUTMENT ;
    PORT
      LAYER met3 ;
      RECT 0.000 1207.680 0.300 1207.980 ;
    END
  END rd_out[92]
  PIN rd_out[93]
    DIRECTION OUTPUT ;
    USE SIGNAL ;
    SHAPE ABUTMENT ;
    PORT
      LAYER met3 ;
      RECT 0.000 1210.400 0.300 1210.700 ;
    END
  END rd_out[93]
  PIN rd_out[94]
    DIRECTION OUTPUT ;
    USE SIGNAL ;
    SHAPE ABUTMENT ;
    PORT
      LAYER met3 ;
      RECT 0.000 1213.120 0.300 1213.420 ;
    END
  END rd_out[94]
  PIN rd_out[95]
    DIRECTION OUTPUT ;
    USE SIGNAL ;
    SHAPE ABUTMENT ;
    PORT
      LAYER met3 ;
      RECT 0.000 1215.840 0.300 1216.140 ;
    END
  END rd_out[95]
  PIN rd_out[96]
    DIRECTION OUTPUT ;
    USE SIGNAL ;
    SHAPE ABUTMENT ;
    PORT
      LAYER met3 ;
      RECT 0.000 1218.560 0.300 1218.860 ;
    END
  END rd_out[96]
  PIN rd_out[97]
    DIRECTION OUTPUT ;
    USE SIGNAL ;
    SHAPE ABUTMENT ;
    PORT
      LAYER met3 ;
      RECT 0.000 1221.280 0.300 1221.580 ;
    END
  END rd_out[97]
  PIN rd_out[98]
    DIRECTION OUTPUT ;
    USE SIGNAL ;
    SHAPE ABUTMENT ;
    PORT
      LAYER met3 ;
      RECT 0.000 1224.000 0.300 1224.300 ;
    END
  END rd_out[98]
  PIN rd_out[99]
    DIRECTION OUTPUT ;
    USE SIGNAL ;
    SHAPE ABUTMENT ;
    PORT
      LAYER met3 ;
      RECT 0.000 1226.720 0.300 1227.020 ;
    END
  END rd_out[99]
  PIN rd_out[100]
    DIRECTION OUTPUT ;
    USE SIGNAL ;
    SHAPE ABUTMENT ;
    PORT
      LAYER met3 ;
      RECT 0.000 1229.440 0.300 1229.740 ;
    END
  END rd_out[100]
  PIN rd_out[101]
    DIRECTION OUTPUT ;
    USE SIGNAL ;
    SHAPE ABUTMENT ;
    PORT
      LAYER met3 ;
      RECT 0.000 1232.160 0.300 1232.460 ;
    END
  END rd_out[101]
  PIN rd_out[102]
    DIRECTION OUTPUT ;
    USE SIGNAL ;
    SHAPE ABUTMENT ;
    PORT
      LAYER met3 ;
      RECT 0.000 1234.880 0.300 1235.180 ;
    END
  END rd_out[102]
  PIN rd_out[103]
    DIRECTION OUTPUT ;
    USE SIGNAL ;
    SHAPE ABUTMENT ;
    PORT
      LAYER met3 ;
      RECT 0.000 1237.600 0.300 1237.900 ;
    END
  END rd_out[103]
  PIN rd_out[104]
    DIRECTION OUTPUT ;
    USE SIGNAL ;
    SHAPE ABUTMENT ;
    PORT
      LAYER met3 ;
      RECT 0.000 1240.320 0.300 1240.620 ;
    END
  END rd_out[104]
  PIN rd_out[105]
    DIRECTION OUTPUT ;
    USE SIGNAL ;
    SHAPE ABUTMENT ;
    PORT
      LAYER met3 ;
      RECT 0.000 1243.040 0.300 1243.340 ;
    END
  END rd_out[105]
  PIN rd_out[106]
    DIRECTION OUTPUT ;
    USE SIGNAL ;
    SHAPE ABUTMENT ;
    PORT
      LAYER met3 ;
      RECT 0.000 1245.760 0.300 1246.060 ;
    END
  END rd_out[106]
  PIN rd_out[107]
    DIRECTION OUTPUT ;
    USE SIGNAL ;
    SHAPE ABUTMENT ;
    PORT
      LAYER met3 ;
      RECT 0.000 1248.480 0.300 1248.780 ;
    END
  END rd_out[107]
  PIN rd_out[108]
    DIRECTION OUTPUT ;
    USE SIGNAL ;
    SHAPE ABUTMENT ;
    PORT
      LAYER met3 ;
      RECT 0.000 1251.200 0.300 1251.500 ;
    END
  END rd_out[108]
  PIN rd_out[109]
    DIRECTION OUTPUT ;
    USE SIGNAL ;
    SHAPE ABUTMENT ;
    PORT
      LAYER met3 ;
      RECT 0.000 1253.920 0.300 1254.220 ;
    END
  END rd_out[109]
  PIN rd_out[110]
    DIRECTION OUTPUT ;
    USE SIGNAL ;
    SHAPE ABUTMENT ;
    PORT
      LAYER met3 ;
      RECT 0.000 1256.640 0.300 1256.940 ;
    END
  END rd_out[110]
  PIN rd_out[111]
    DIRECTION OUTPUT ;
    USE SIGNAL ;
    SHAPE ABUTMENT ;
    PORT
      LAYER met3 ;
      RECT 0.000 1259.360 0.300 1259.660 ;
    END
  END rd_out[111]
  PIN rd_out[112]
    DIRECTION OUTPUT ;
    USE SIGNAL ;
    SHAPE ABUTMENT ;
    PORT
      LAYER met3 ;
      RECT 0.000 1262.080 0.300 1262.380 ;
    END
  END rd_out[112]
  PIN rd_out[113]
    DIRECTION OUTPUT ;
    USE SIGNAL ;
    SHAPE ABUTMENT ;
    PORT
      LAYER met3 ;
      RECT 0.000 1264.800 0.300 1265.100 ;
    END
  END rd_out[113]
  PIN rd_out[114]
    DIRECTION OUTPUT ;
    USE SIGNAL ;
    SHAPE ABUTMENT ;
    PORT
      LAYER met3 ;
      RECT 0.000 1267.520 0.300 1267.820 ;
    END
  END rd_out[114]
  PIN rd_out[115]
    DIRECTION OUTPUT ;
    USE SIGNAL ;
    SHAPE ABUTMENT ;
    PORT
      LAYER met3 ;
      RECT 0.000 1270.240 0.300 1270.540 ;
    END
  END rd_out[115]
  PIN rd_out[116]
    DIRECTION OUTPUT ;
    USE SIGNAL ;
    SHAPE ABUTMENT ;
    PORT
      LAYER met3 ;
      RECT 0.000 1272.960 0.300 1273.260 ;
    END
  END rd_out[116]
  PIN rd_out[117]
    DIRECTION OUTPUT ;
    USE SIGNAL ;
    SHAPE ABUTMENT ;
    PORT
      LAYER met3 ;
      RECT 0.000 1275.680 0.300 1275.980 ;
    END
  END rd_out[117]
  PIN rd_out[118]
    DIRECTION OUTPUT ;
    USE SIGNAL ;
    SHAPE ABUTMENT ;
    PORT
      LAYER met3 ;
      RECT 0.000 1278.400 0.300 1278.700 ;
    END
  END rd_out[118]
  PIN rd_out[119]
    DIRECTION OUTPUT ;
    USE SIGNAL ;
    SHAPE ABUTMENT ;
    PORT
      LAYER met3 ;
      RECT 0.000 1281.120 0.300 1281.420 ;
    END
  END rd_out[119]
  PIN rd_out[120]
    DIRECTION OUTPUT ;
    USE SIGNAL ;
    SHAPE ABUTMENT ;
    PORT
      LAYER met3 ;
      RECT 0.000 1283.840 0.300 1284.140 ;
    END
  END rd_out[120]
  PIN rd_out[121]
    DIRECTION OUTPUT ;
    USE SIGNAL ;
    SHAPE ABUTMENT ;
    PORT
      LAYER met3 ;
      RECT 0.000 1286.560 0.300 1286.860 ;
    END
  END rd_out[121]
  PIN rd_out[122]
    DIRECTION OUTPUT ;
    USE SIGNAL ;
    SHAPE ABUTMENT ;
    PORT
      LAYER met3 ;
      RECT 0.000 1289.280 0.300 1289.580 ;
    END
  END rd_out[122]
  PIN rd_out[123]
    DIRECTION OUTPUT ;
    USE SIGNAL ;
    SHAPE ABUTMENT ;
    PORT
      LAYER met3 ;
      RECT 0.000 1292.000 0.300 1292.300 ;
    END
  END rd_out[123]
  PIN rd_out[124]
    DIRECTION OUTPUT ;
    USE SIGNAL ;
    SHAPE ABUTMENT ;
    PORT
      LAYER met3 ;
      RECT 0.000 1294.720 0.300 1295.020 ;
    END
  END rd_out[124]
  PIN rd_out[125]
    DIRECTION OUTPUT ;
    USE SIGNAL ;
    SHAPE ABUTMENT ;
    PORT
      LAYER met3 ;
      RECT 0.000 1297.440 0.300 1297.740 ;
    END
  END rd_out[125]
  PIN rd_out[126]
    DIRECTION OUTPUT ;
    USE SIGNAL ;
    SHAPE ABUTMENT ;
    PORT
      LAYER met3 ;
      RECT 0.000 1300.160 0.300 1300.460 ;
    END
  END rd_out[126]
  PIN rd_out[127]
    DIRECTION OUTPUT ;
    USE SIGNAL ;
    SHAPE ABUTMENT ;
    PORT
      LAYER met3 ;
      RECT 0.000 1302.880 0.300 1303.180 ;
    END
  END rd_out[127]
  PIN rd_out[128]
    DIRECTION OUTPUT ;
    USE SIGNAL ;
    SHAPE ABUTMENT ;
    PORT
      LAYER met3 ;
      RECT 0.000 1305.600 0.300 1305.900 ;
    END
  END rd_out[128]
  PIN rd_out[129]
    DIRECTION OUTPUT ;
    USE SIGNAL ;
    SHAPE ABUTMENT ;
    PORT
      LAYER met3 ;
      RECT 0.000 1308.320 0.300 1308.620 ;
    END
  END rd_out[129]
  PIN rd_out[130]
    DIRECTION OUTPUT ;
    USE SIGNAL ;
    SHAPE ABUTMENT ;
    PORT
      LAYER met3 ;
      RECT 0.000 1311.040 0.300 1311.340 ;
    END
  END rd_out[130]
  PIN rd_out[131]
    DIRECTION OUTPUT ;
    USE SIGNAL ;
    SHAPE ABUTMENT ;
    PORT
      LAYER met3 ;
      RECT 0.000 1313.760 0.300 1314.060 ;
    END
  END rd_out[131]
  PIN rd_out[132]
    DIRECTION OUTPUT ;
    USE SIGNAL ;
    SHAPE ABUTMENT ;
    PORT
      LAYER met3 ;
      RECT 0.000 1316.480 0.300 1316.780 ;
    END
  END rd_out[132]
  PIN rd_out[133]
    DIRECTION OUTPUT ;
    USE SIGNAL ;
    SHAPE ABUTMENT ;
    PORT
      LAYER met3 ;
      RECT 0.000 1319.200 0.300 1319.500 ;
    END
  END rd_out[133]
  PIN rd_out[134]
    DIRECTION OUTPUT ;
    USE SIGNAL ;
    SHAPE ABUTMENT ;
    PORT
      LAYER met3 ;
      RECT 0.000 1321.920 0.300 1322.220 ;
    END
  END rd_out[134]
  PIN rd_out[135]
    DIRECTION OUTPUT ;
    USE SIGNAL ;
    SHAPE ABUTMENT ;
    PORT
      LAYER met3 ;
      RECT 0.000 1324.640 0.300 1324.940 ;
    END
  END rd_out[135]
  PIN rd_out[136]
    DIRECTION OUTPUT ;
    USE SIGNAL ;
    SHAPE ABUTMENT ;
    PORT
      LAYER met3 ;
      RECT 0.000 1327.360 0.300 1327.660 ;
    END
  END rd_out[136]
  PIN rd_out[137]
    DIRECTION OUTPUT ;
    USE SIGNAL ;
    SHAPE ABUTMENT ;
    PORT
      LAYER met3 ;
      RECT 0.000 1330.080 0.300 1330.380 ;
    END
  END rd_out[137]
  PIN rd_out[138]
    DIRECTION OUTPUT ;
    USE SIGNAL ;
    SHAPE ABUTMENT ;
    PORT
      LAYER met3 ;
      RECT 0.000 1332.800 0.300 1333.100 ;
    END
  END rd_out[138]
  PIN rd_out[139]
    DIRECTION OUTPUT ;
    USE SIGNAL ;
    SHAPE ABUTMENT ;
    PORT
      LAYER met3 ;
      RECT 0.000 1335.520 0.300 1335.820 ;
    END
  END rd_out[139]
  PIN rd_out[140]
    DIRECTION OUTPUT ;
    USE SIGNAL ;
    SHAPE ABUTMENT ;
    PORT
      LAYER met3 ;
      RECT 0.000 1338.240 0.300 1338.540 ;
    END
  END rd_out[140]
  PIN rd_out[141]
    DIRECTION OUTPUT ;
    USE SIGNAL ;
    SHAPE ABUTMENT ;
    PORT
      LAYER met3 ;
      RECT 0.000 1340.960 0.300 1341.260 ;
    END
  END rd_out[141]
  PIN rd_out[142]
    DIRECTION OUTPUT ;
    USE SIGNAL ;
    SHAPE ABUTMENT ;
    PORT
      LAYER met3 ;
      RECT 0.000 1343.680 0.300 1343.980 ;
    END
  END rd_out[142]
  PIN rd_out[143]
    DIRECTION OUTPUT ;
    USE SIGNAL ;
    SHAPE ABUTMENT ;
    PORT
      LAYER met3 ;
      RECT 0.000 1346.400 0.300 1346.700 ;
    END
  END rd_out[143]
  PIN rd_out[144]
    DIRECTION OUTPUT ;
    USE SIGNAL ;
    SHAPE ABUTMENT ;
    PORT
      LAYER met3 ;
      RECT 0.000 1349.120 0.300 1349.420 ;
    END
  END rd_out[144]
  PIN rd_out[145]
    DIRECTION OUTPUT ;
    USE SIGNAL ;
    SHAPE ABUTMENT ;
    PORT
      LAYER met3 ;
      RECT 0.000 1351.840 0.300 1352.140 ;
    END
  END rd_out[145]
  PIN rd_out[146]
    DIRECTION OUTPUT ;
    USE SIGNAL ;
    SHAPE ABUTMENT ;
    PORT
      LAYER met3 ;
      RECT 0.000 1354.560 0.300 1354.860 ;
    END
  END rd_out[146]
  PIN rd_out[147]
    DIRECTION OUTPUT ;
    USE SIGNAL ;
    SHAPE ABUTMENT ;
    PORT
      LAYER met3 ;
      RECT 0.000 1357.280 0.300 1357.580 ;
    END
  END rd_out[147]
  PIN rd_out[148]
    DIRECTION OUTPUT ;
    USE SIGNAL ;
    SHAPE ABUTMENT ;
    PORT
      LAYER met3 ;
      RECT 0.000 1360.000 0.300 1360.300 ;
    END
  END rd_out[148]
  PIN rd_out[149]
    DIRECTION OUTPUT ;
    USE SIGNAL ;
    SHAPE ABUTMENT ;
    PORT
      LAYER met3 ;
      RECT 0.000 1362.720 0.300 1363.020 ;
    END
  END rd_out[149]
  PIN rd_out[150]
    DIRECTION OUTPUT ;
    USE SIGNAL ;
    SHAPE ABUTMENT ;
    PORT
      LAYER met3 ;
      RECT 0.000 1365.440 0.300 1365.740 ;
    END
  END rd_out[150]
  PIN rd_out[151]
    DIRECTION OUTPUT ;
    USE SIGNAL ;
    SHAPE ABUTMENT ;
    PORT
      LAYER met3 ;
      RECT 0.000 1368.160 0.300 1368.460 ;
    END
  END rd_out[151]
  PIN rd_out[152]
    DIRECTION OUTPUT ;
    USE SIGNAL ;
    SHAPE ABUTMENT ;
    PORT
      LAYER met3 ;
      RECT 0.000 1370.880 0.300 1371.180 ;
    END
  END rd_out[152]
  PIN rd_out[153]
    DIRECTION OUTPUT ;
    USE SIGNAL ;
    SHAPE ABUTMENT ;
    PORT
      LAYER met3 ;
      RECT 0.000 1373.600 0.300 1373.900 ;
    END
  END rd_out[153]
  PIN rd_out[154]
    DIRECTION OUTPUT ;
    USE SIGNAL ;
    SHAPE ABUTMENT ;
    PORT
      LAYER met3 ;
      RECT 0.000 1376.320 0.300 1376.620 ;
    END
  END rd_out[154]
  PIN rd_out[155]
    DIRECTION OUTPUT ;
    USE SIGNAL ;
    SHAPE ABUTMENT ;
    PORT
      LAYER met3 ;
      RECT 0.000 1379.040 0.300 1379.340 ;
    END
  END rd_out[155]
  PIN rd_out[156]
    DIRECTION OUTPUT ;
    USE SIGNAL ;
    SHAPE ABUTMENT ;
    PORT
      LAYER met3 ;
      RECT 0.000 1381.760 0.300 1382.060 ;
    END
  END rd_out[156]
  PIN rd_out[157]
    DIRECTION OUTPUT ;
    USE SIGNAL ;
    SHAPE ABUTMENT ;
    PORT
      LAYER met3 ;
      RECT 0.000 1384.480 0.300 1384.780 ;
    END
  END rd_out[157]
  PIN rd_out[158]
    DIRECTION OUTPUT ;
    USE SIGNAL ;
    SHAPE ABUTMENT ;
    PORT
      LAYER met3 ;
      RECT 0.000 1387.200 0.300 1387.500 ;
    END
  END rd_out[158]
  PIN rd_out[159]
    DIRECTION OUTPUT ;
    USE SIGNAL ;
    SHAPE ABUTMENT ;
    PORT
      LAYER met3 ;
      RECT 0.000 1389.920 0.300 1390.220 ;
    END
  END rd_out[159]
  PIN rd_out[160]
    DIRECTION OUTPUT ;
    USE SIGNAL ;
    SHAPE ABUTMENT ;
    PORT
      LAYER met3 ;
      RECT 0.000 1392.640 0.300 1392.940 ;
    END
  END rd_out[160]
  PIN rd_out[161]
    DIRECTION OUTPUT ;
    USE SIGNAL ;
    SHAPE ABUTMENT ;
    PORT
      LAYER met3 ;
      RECT 0.000 1395.360 0.300 1395.660 ;
    END
  END rd_out[161]
  PIN rd_out[162]
    DIRECTION OUTPUT ;
    USE SIGNAL ;
    SHAPE ABUTMENT ;
    PORT
      LAYER met3 ;
      RECT 0.000 1398.080 0.300 1398.380 ;
    END
  END rd_out[162]
  PIN rd_out[163]
    DIRECTION OUTPUT ;
    USE SIGNAL ;
    SHAPE ABUTMENT ;
    PORT
      LAYER met3 ;
      RECT 0.000 1400.800 0.300 1401.100 ;
    END
  END rd_out[163]
  PIN rd_out[164]
    DIRECTION OUTPUT ;
    USE SIGNAL ;
    SHAPE ABUTMENT ;
    PORT
      LAYER met3 ;
      RECT 0.000 1403.520 0.300 1403.820 ;
    END
  END rd_out[164]
  PIN rd_out[165]
    DIRECTION OUTPUT ;
    USE SIGNAL ;
    SHAPE ABUTMENT ;
    PORT
      LAYER met3 ;
      RECT 0.000 1406.240 0.300 1406.540 ;
    END
  END rd_out[165]
  PIN rd_out[166]
    DIRECTION OUTPUT ;
    USE SIGNAL ;
    SHAPE ABUTMENT ;
    PORT
      LAYER met3 ;
      RECT 0.000 1408.960 0.300 1409.260 ;
    END
  END rd_out[166]
  PIN rd_out[167]
    DIRECTION OUTPUT ;
    USE SIGNAL ;
    SHAPE ABUTMENT ;
    PORT
      LAYER met3 ;
      RECT 0.000 1411.680 0.300 1411.980 ;
    END
  END rd_out[167]
  PIN rd_out[168]
    DIRECTION OUTPUT ;
    USE SIGNAL ;
    SHAPE ABUTMENT ;
    PORT
      LAYER met3 ;
      RECT 0.000 1414.400 0.300 1414.700 ;
    END
  END rd_out[168]
  PIN rd_out[169]
    DIRECTION OUTPUT ;
    USE SIGNAL ;
    SHAPE ABUTMENT ;
    PORT
      LAYER met3 ;
      RECT 0.000 1417.120 0.300 1417.420 ;
    END
  END rd_out[169]
  PIN rd_out[170]
    DIRECTION OUTPUT ;
    USE SIGNAL ;
    SHAPE ABUTMENT ;
    PORT
      LAYER met3 ;
      RECT 0.000 1419.840 0.300 1420.140 ;
    END
  END rd_out[170]
  PIN rd_out[171]
    DIRECTION OUTPUT ;
    USE SIGNAL ;
    SHAPE ABUTMENT ;
    PORT
      LAYER met3 ;
      RECT 0.000 1422.560 0.300 1422.860 ;
    END
  END rd_out[171]
  PIN rd_out[172]
    DIRECTION OUTPUT ;
    USE SIGNAL ;
    SHAPE ABUTMENT ;
    PORT
      LAYER met3 ;
      RECT 0.000 1425.280 0.300 1425.580 ;
    END
  END rd_out[172]
  PIN rd_out[173]
    DIRECTION OUTPUT ;
    USE SIGNAL ;
    SHAPE ABUTMENT ;
    PORT
      LAYER met3 ;
      RECT 0.000 1428.000 0.300 1428.300 ;
    END
  END rd_out[173]
  PIN clk
    DIRECTION INPUT ;
    USE SIGNAL ;
    SHAPE ABUTMENT ;
    PORT
      LAYER met3 ;
      RECT 0.000 1430.720 0.300 1431.020 ;
    END
  END clk
  PIN ce_in
    DIRECTION INPUT ;
    USE SIGNAL ;
    SHAPE ABUTMENT ;
    PORT
      LAYER met3 ;
      RECT 0.000 1433.440 0.300 1433.740 ;
    END
  END ce_in
  PIN we_in
    DIRECTION INPUT ;
    USE SIGNAL ;
    SHAPE ABUTMENT ;
    PORT
      LAYER met3 ;
      RECT 0.000 1436.160 0.300 1436.460 ;
    END
  END we_in
  OBS
    LAYER met1 ;
      RECT 0.000 0.000 166.980 1447.040 ;
    LAYER met2 ;
      RECT 0.000 0.000 166.980 1447.040 ;
    LAYER met3 ;
      RECT 0.000 0.000 166.980 1447.040 ;
  END
END fakeram_8x174_1rw
END LIBRARY
